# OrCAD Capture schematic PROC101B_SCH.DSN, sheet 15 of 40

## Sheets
15 38. SoC POWER SUPPLY: size C; title: SoC POWER SUPPLY

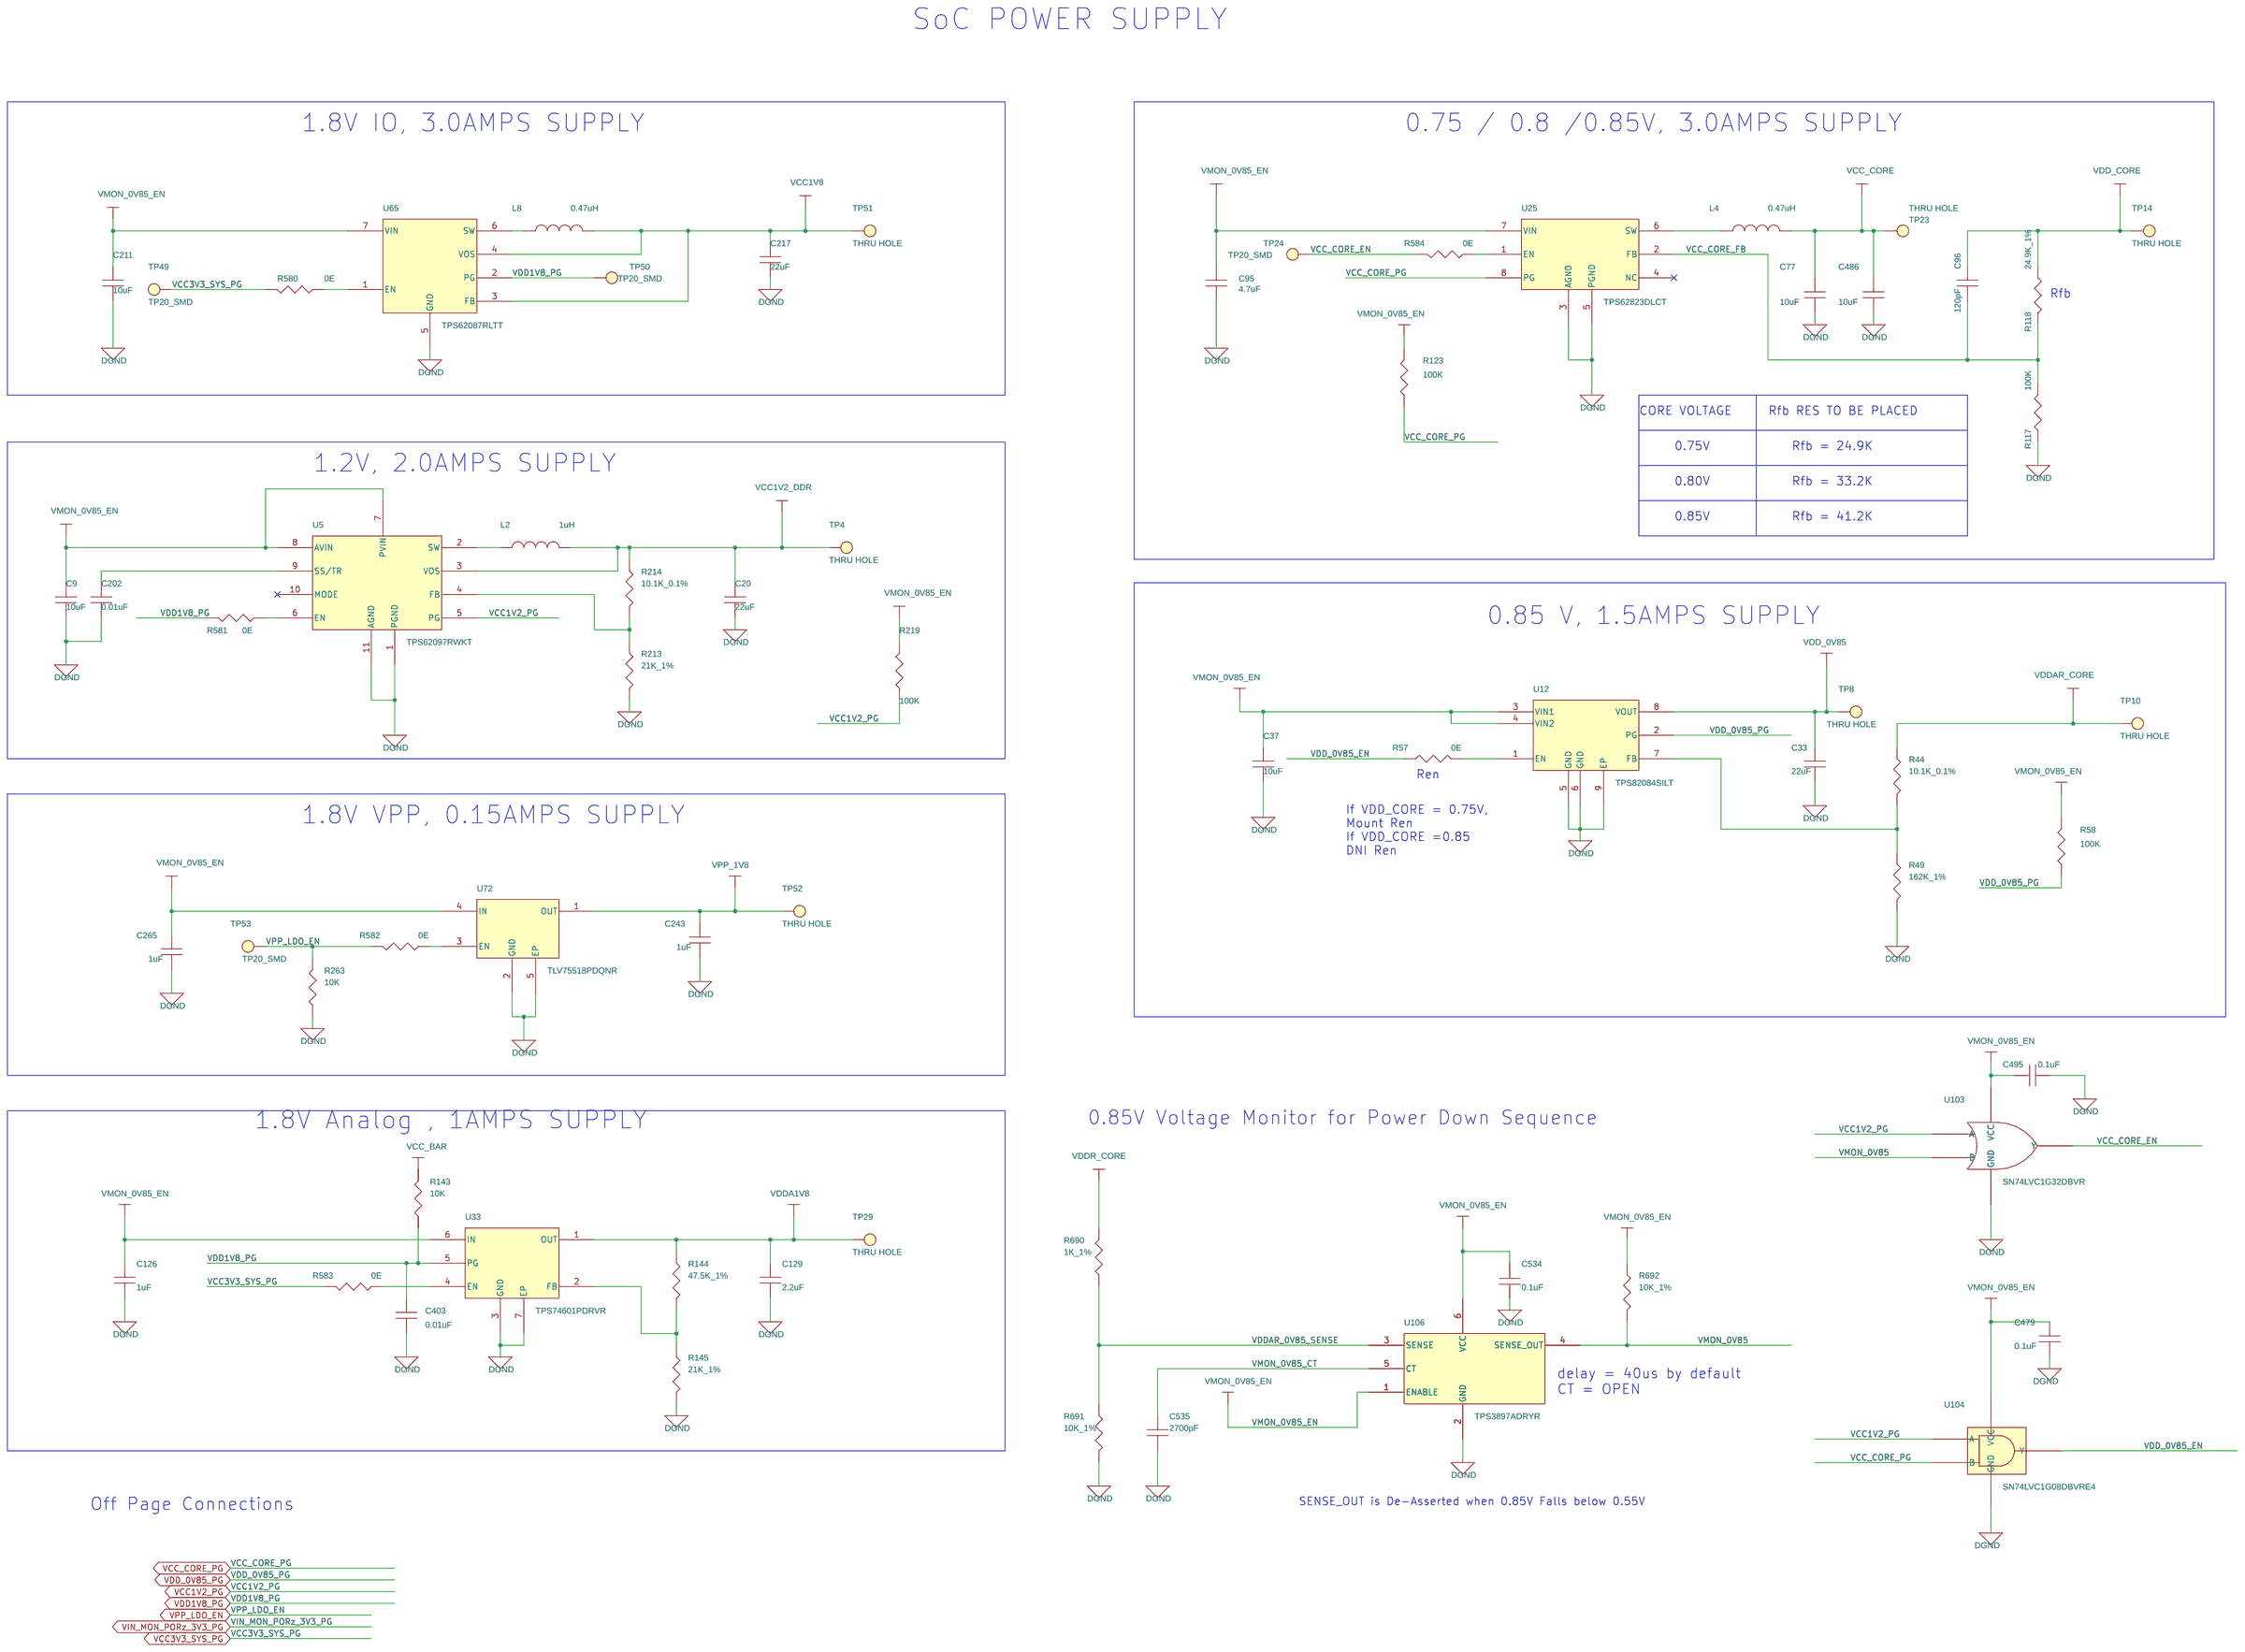
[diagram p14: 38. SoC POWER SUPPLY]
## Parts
C9  10uF  [CAP0402_0-75]
C20  22uF  [CAP0603_1]
C33  22uF  [CAP0603_1]
C37  10uF  [CAP0402_0-75]
C77  10uF  [CAP0402_0-75]
C95  4.7uF  [CAP0603_1]
C96  120pF  [CAP0402_0-75]
C126  1uF  [CAP0402_0-75]
C129  2.2uF  [CAP0402_0-75]
C202  0.01uF  [CAP0402_0-75]
C211  10uF  [CAP0603_1]
C217  22uF  [CAP0603_1]
C243  1uF  [CAP0402_0-75]
C265  1uF  [CAP0402_0-75]
C403  0.01uF  [CAP0402_0-75]
C479  0.1uF  [CAP0402_0-75]
C486  10uF  [CAP0402_0-75]
C495  0.1uF  [CAP0402_0-75]
C534  0.1uF  [CAP0402_0-75]
C535  2700pF  [CAP0603_1]
L2  1uH  [IND_744316100_230X220_SMD_4-3]
L4  0.47uH  [IND_744373460047_270X270_SMD_3]
L8  0.47uH  [IND_744373460047_270X270_SMD_3]
R44  10.1K_0.1%  [RES0603_0-75]
R49  162K_1%  [RES0402_0-5]
R57  0E  [RES0402_0-5]
R58  100K  [RES0402_0-5]
R117  100K  [RES0402_0-5]
R118  24.9K_1%  [RES0402_0-5]
R123  100K  [RES0402_0-5]
R143  10K  [RES0402_0-5]
R144  47.5K_1%  [RES0402_0-5]
R145  21K_1%  [RES0402_0-5]
R213  21K_1%  [RES0402_0-5]
R214  10.1K_0.1%  [RES0603_0-75]
R219  100K  [RES0402_0-5]
R263  10K  [RES0402_0-5]
R580  0E  [RES0402_0-5]
R581  0E  [RES0402_0-5]
R582  0E  [RES0402_0-5]
R583  0E  [RES0402_0-5]
R584  0E  [RES0402_0-5]
R690  1K_1%  [RES0402_0-5]
R691  10K_1%  [RES0402_0-5]
R692  10K_1%  [RES0402_0-5]
TP4  THRU HOLE  [TP_40X65]
TP8  THRU HOLE  [TP_40X65]
TP10  THRU HOLE  [TP_40X65]
TP14  THRU HOLE  [TP_40X65]
TP23  THRU HOLE  [TP_40X65]
TP24  TP20_SMD  [TP20_SMD]
TP29  THRU HOLE  [TP_40X65]
TP49  TP20_SMD  [TP20_SMD]
TP50  TP20_SMD  [TP20_SMD]
TP51  THRU HOLE  [TP_40X65]
TP52  THRU HOLE  [TP_40X65]
TP53  TP20_SMD  [TP20_SMD]
U5  TPS62097RWKT  [VQFNHR11_TPS62097_80X80_1]
U12  TPS82084SILT  [uSIP8_TPS82084_110X120_1-4]
U25  TPS62823DLCT  [VSONHR8_TPS62823_60X80_1]
U33  TPS74601PDRVR  [SON6_25-59_85X85_0-8]
U65  TPS62087RLTT  [VSONHR7_TPS62085_80X80_1]
U72  TLV75518PDQNR  [X2SON4_TLV71318P_40X40_0-4]
U103  SN74LVC1G32DBVR  [SOT23-5_1-5]
U104  SN74LVC1G08DBVRE4  [SOT23-5]
U106  TPS3897ADRYR  [SON6_19-68_40X60_0-6]

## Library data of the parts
C9 C37 C77 C486 = CAP: CAP CERAMIC 10uF 10V 20% X5R 0402; Chkd/date: MANIRAJA/300520; Crtd /date: ALVY/260520; Custom_Duty: 15%; Customs_HS_Code: 85322990; Distributor_name: DIGIKEY; Distributor_part_number: 490-GRM155R61A106ME11DTR-ND; Footprint Path: Y:\MIS_DATABASE\Library\ALTIUM_TOOL\PCB_FOOTPRINTS\Altium_Footprint_Lib.PcbLib; Height: 0.55MM; Library Path: Y:\MIS_DATABASE\Library\ALTIUM_TOOL\SCHEMATICS_PARTS\MS_DISCRETE_Library.schlib; Mfr_name: MURATA; Mfr_part_number: GRM155R61A106ME11D; Mistral Part No: 120013110019-R; Package: 0402; Part_type: CAPACITORS\CERAMIC; Project: QCS610_NANOSOM; RoHS: RoHS; Temperature: -55°C+85°C; Tolerance: 20%; Voltage: 10V; Wattage: NA; Weight: 3.1mg; Datasheet: Y:\MIS_DATABASE\DATASHEETS\CAPACITORS\MURATA-GXX-SER_NOV17.PDF
C20 C33 C217 = CAP: CAP CERAMIC 22uF 6.3V 20% X5R 0603; Chkd/date: JEBRAN/090915; Crtd /date: JEBRAN/090915; Custom_Duty: 15%; Customs_HS_Code: 85322990; Distributor_name: DIGIKEY; Distributor_part_number: 490-7611-2-ND; Footprint Path: Y:\MIS_DATABASE\Library\ALTIUM_TOOL\PCB_FOOTPRINTS\Altium_Footprint_Lib.PcbLib; Height: 1.00MM; Library Path: Y:\MIS_DATABASE\Library\ALTIUM_TOOL\SCHEMATICS_PARTS\MS_DISCRETE_Library.schlib; Mfr_name: MURATA; Mfr_part_number: GRM188R60J226MEA0; Mistral Part No: 120015090007-R; Package: 0603; Part_type: CAPACITORS\CERAMIC; Project: OCTBTS_3000; RoHS: RoHS; Temperature: -55°C+85°C; Tolerance: 20%; Voltage: 6.3V; Wattage: NA; Weight: 6.3mg; Datasheet: Y:\MIS_DATABASE\DATASHEETS\CAPACITORS\MURATA-GXX-SER_NOV17.PDF
C95 = CAP: CAP CERAMIC 4.7uF 16V 10% X5R 0603; Chkd/date: MANIRAJA/131217; Crtd /date: ALVY/131217; Custom_Duty: 15%; Customs_HS_Code: 85322990; Distributor_name: DIGIKEY; Distributor_part_number: 311-1785-1-ND; Footprint Path: Y:\MIS_DATABASE\Library\ALTIUM_TOOL\PCB_FOOTPRINTS\Altium_Footprint_Lib.PcbLib; Height: 0.95MM; Library Path: Y:\MIS_DATABASE\Library\ALTIUM_TOOL\SCHEMATICS_PARTS\MS_DISCRETE_Library.schlib; Mfr_name: YAGEO AMERICA; Mfr_part_number: CC0603KRX5R7BB475; Mistral Part No: 120011050004-R; Package: 0603; Part_type: CAPACITORS\CERAMIC; Project: ASL_LIU_TYPE-II; RoHS: RoHS; Temperature: -55°C+85°C; Tolerance: 10%; Voltage: 16V; Wattage: NA; Weight: 2mg; Datasheet: Y:\MIS_DATABASE\DATASHEETS\CAPACITORS\YACC-X5R.PDF
C96 = CAP: CAP CERAMIC 120pF 50V 5% C0G(NP0) 0402; Chkd/date: MANIRAJA/080520; Crtd /date: ALVY/070520; Custom_Duty: 15%; Customs_HS_Code: 85322990; Distributor_name: DIGIKEY; Distributor_part_number: 311-3337-1-ND; Footprint Path: Y:\MIS_DATABASE\Library\ALTIUM_TOOL\PCB_FOOTPRINTS\Altium_Footprint_Lib.PcbLib; Height: 0.55MM; Library Path: Y:\MIS_DATABASE\Library\ALTIUM_TOOL\SCHEMATICS_PARTS\MS_DISCRETE_Library.schlib; Mfr_name: YAGEO AMERICA; Mfr_part_number: CC0402JRNPO9BN121; Mistral Part No: 120014040005-R; Package: 0402; Part_type: CAPACITORS\CERAMIC; Project: AM64x-GP_EVM BRD; RoHS: RoHS; Temperature: -55°C+125°C; Tolerance: 5%; Voltage: 50V; Wattage: NA; Weight: 12mg; Datasheet: Y:\MIS_DATABASE\DATASHEETS\CAPACITORS\YACC-NPO.PDF
C126 C243 C265 = CAP: CAP CERAMIC 1uF 10V 20% X5R 0402; Chkd/date: MANIRAJA/210820; Crtd /date: ALVY/190820; Custom_Duty: 15%; Customs_HS_Code: 85322990; Distributor_name: DIGIKEY; Distributor_part_number: 732-7489-1-ND; Footprint Path: Y:\MIS_DATABASE\Library\ALTIUM_TOOL\PCB_FOOTPRINTS\Altium_Footprint_Lib.PcbLib; Height: 0.55MM; Library Path: Y:\MIS_DATABASE\Library\ALTIUM_TOOL\SCHEMATICS_PARTS\MS_DISCRETE_Library.schlib; Mfr_name: WURTH ELECTRONICS; Mfr_part_number: 885012105012; Mistral Part No: 120020080009-R; Package: 0402; Part_type: CAPACITORS\CERAMIC; Project: AM64x_EVM_BRD; RoHS: RoHS; Temperature: -55°C+85°C; Tolerance: 20%; Voltage: 10V; Wattage: NA; Weight: 0.65mg; Datasheet: Y:\MIS_DATABASE\DATASHEETS\CAPACITORS\885012105012.PDF
C129 = CAP: CAP CERAMIC 2.2uF 10V 20% X5R 0402; Chkd/date: MANIRAJA/170820; Crtd /date: ALVY/170820; Custom_Duty: 15%; Customs_HS_Code: 85322990; Distributor_name: DIGIKEY; Distributor_part_number: 732-7490-1-ND; Footprint Path: Y:\MIS_DATABASE\Library\ALTIUM_TOOL\PCB_FOOTPRINTS\Altium_Footprint_Lib.PcbLib; Height: 0.55MM; Library Path: Y:\MIS_DATABASE\Library\ALTIUM_TOOL\SCHEMATICS_PARTS\MS_DISCRETE_Library.schlib; Mfr_name: WURTH ELECTRONICS; Mfr_part_number: 885012105013; Mistral Part No: 120019040036-R; Package: 0402; Part_type: CAPACITORS\CERAMIC; Project: AM64x_EVM_BRD; RoHS: RoHS; Temperature: -55°C+85°C; Tolerance: 20%; Voltage: 10V; Wattage: NA; Weight: 0.65mg; Datasheet: Y:\MIS_DATABASE\DATASHEETS\CAPACITORS\885012105013.PDF
C202 C403 = CAP: CAP CERAMIC 0.01uF 25V 10% X7R 0402; Chkd/date: MANIRAJA/170820; Crtd /date: ALVY/170820; Custom_Duty: 15%; Customs_HS_Code: 85322990; Distributor_name: DIGIKEY; Distributor_part_number: 732-7545-1-ND; Footprint Path: Y:\MIS_DATABASE\Library\ALTIUM_TOOL\PCB_FOOTPRINTS\Altium_Footprint_Lib.PcbLib; Height: 0.55MM; Library Path: Y:\MIS_DATABASE\Library\ALTIUM_TOOL\SCHEMATICS_PARTS\MS_DISCRETE_Library.schlib; Mfr_name: WURTH ELECTRONICS; Mfr_part_number: 885012205050; Mistral Part No: 120011090040-R; Package: 0402; Part_type: CAPACITORS\CERAMIC; Project: AM64x_EVM_BRD; RoHS: RoHS; Temperature: -55°C+125°C; Tolerance: 10%; Voltage: 25V; Wattage: NA; Weight: 0.65mg; Datasheet: Y:\MIS_DATABASE\DATASHEETS\CAPACITORS\885012205050.PDF
C211 = CAP: CAP CERAMIC 10uF 35V 20% X5R 0603; Chkd/date: MANIRAJA/170519; Crtd /date: ALVY/160519; Custom_Duty: 15%; Customs_HS_Code: 85322990; Distributor_name: DIGIKEY; Distributor_part_number: 490-13248-1-ND; Footprint Path: Y:\MIS_DATABASE\Library\ALTIUM_TOOL\PCB_FOOTPRINTS\Altium_Footprint_Lib.PcbLib; Height: 1.00MM; Library Path: Y:\MIS_DATABASE\Library\ALTIUM_TOOL\SCHEMATICS_PARTS\MS_DISCRETE_Library.schlib; Mfr_name: MURATA; Mfr_part_number: GRM188R6YA106MA73D; Mistral Part No: 120019050016-R; Package: 0603; Part_type: CAPACITORS\CERAMIC; Project: BRUKER_SD820_COMMONDO; RoHS: RoHS; Temperature: -55°C+85°C; Tolerance: 20%; Voltage: 35V; Wattage: NA; Weight: 9mg; Datasheet: Y:\MIS_DATABASE\DATASHEETS\CAPACITORS\GRM188R6YA106MA73.PDF
C479 C495 C534 = CAP: CAP CERAMIC 0.1uF 25V 20% X5R 0402; Alt_Mfr_name: YAGEO AMERICA; Alt_Mfr_part_number: CC0402KRX5R8BB104; Chkd/date: MANIRAJA/170820; Crtd /date: ALVY/170820; Custom_Duty: 15%; Customs_HS_Code: 85322990; Distributor_name: DIGIKEY; Distributor_part_number: 732-7495-1-ND; Footprint Path: Y:\MIS_DATABASE\Library\ALTIUM_TOOL\PCB_FOOTPRINTS\Altium_Footprint_Lib.PcbLib; Height: 0.55MM; Library Path: Y:\MIS_DATABASE\Library\ALTIUM_TOOL\SCHEMATICS_PARTS\MS_DISCRETE_Library.schlib; Mfr_name: WURTH ELECTRONICS; Mfr_part_number: 885012105018; Mistral Part No: 120020080003-R; Package: 0402; Part_type: CAPACITORS\CERAMIC; Project: AM64x_EVM_BRD; RoHS: RoHS; Temperature: -55°C+85°C; Tolerance: 20%; Voltage: 25V; Wattage: NA; Weight: 0.65mg; Datasheet: Y:\MIS_DATABASE\DATASHEETS\CAPACITORS\885012105018.PDF
C535 = CAP: CAP CERAMIC 2700pF 50V 5% C0G(NP0) 0603; Chkd/date: BAVISH/050911; Crtd /date: CHAITHANYA/290811; Custom_Duty: 15%; Customs_HS_Code: 85322990; Distributor_name: DIGIKEY; Distributor_part_number: 490-3283-1-ND; Footprint Path: Y:\MIS_DATABASE\Library\ALTIUM_TOOL\PCB_FOOTPRINTS\Altium_Footprint_Lib.PcbLib; Height: 0.90MM; Library Path: Y:\MIS_DATABASE\Library\ALTIUM_TOOL\SCHEMATICS_PARTS\MS_DISCRETE_Library.schlib; Mfr_name: MURATA; Mfr_part_number: GRM1885C1H272JA01D; Mistral Part No: 120011090002-R; Package: 0603; Part_type: CAPACITORS\CERAMIC; Project: GEMYC; RoHS: RoHS; Temperature: -55°C+125°C; Tolerance: 5%; Voltage: 50V; Wattage: NA; Weight: 6.3mg; Datasheet: Y:\MIS_DATABASE\DATASHEETS\CAPACITORS\MURATA-GXX-SER_NOV17.PDF
L2 = INDUCTOR: IND HI-CURRENT 1uH 11.5A 20% SMD; Chkd/date: MANIRAJA/280520; Crtd /date: ALVY/280520; Custom_Duty: 24%; Customs_HS_Code: 85437099; Distributor_name: DIGIKEY; Distributor_part_number: 732-6176-1-ND; Footprint Path: Y:\MIS_DATABASE\Library\ALTIUM_TOOL\PCB_FOOTPRINTS\Altium_Footprint_Lib.PcbLib; Height: 4.30MM; Library Path: Y:\MIS_DATABASE\Library\ALTIUM_TOOL\SCHEMATICS_PARTS\MS_DISCRETE_Library.schlib; Mfr_name: WURTH ELECTRONICS; Mfr_part_number: 744316100; Mistral Part No: 130020050041-R; Package: SMD; Project: AM64x-GP_EVM BRD; RoHS: RoHS; Temperature: -40°C+150°C; Tolerance: 20%; Voltage: NA; Wattage: NA; Weight: 570mg; Datasheet: Y:\MIS_DATABASE\DATASHEETS\DISCRETES\INDUCTORS\744316100.PDF
L4 L8 = INDUCTOR: IND POWER 0.47uH 11.5A 20% SMD; Chkd/date: MANIRAJA/130820; Crtd /date: ALVY/130820; Custom_Duty: 24%; Customs_HS_Code: 85437099; Distributor_name: DIGIKEY; Distributor_part_number: 732-3366-1-ND; Footprint Path: Y:\MIS_DATABASE\Library\ALTIUM_TOOL\PCB_FOOTPRINTS\Altium_Footprint_Lib.PcbLib; Height: 3.00MM; Library Path: Y:\MIS_DATABASE\Library\ALTIUM_TOOL\SCHEMATICS_PARTS\MS_DISCRETE_Library.schlib; Mfr_name: WURTH ELECTRONICS; Mfr_part_number: 744373460047; Mistral Part No: 130020080011-R; Package: SMD; Project: AM64x_EVM_BRD; RoHS: RoHS; Temperature: -40°C+125°C; Tolerance: 20%; Voltage: NA; Wattage: NA; Weight: 719mg; Datasheet: Y:\MIS_DATABASE\DATASHEETS\DISCRETES\INDUCTORS\744373460047.PDF
R44 R214 = RESISTOR: RES 10.1K 1/8W 0.1% AUTO 0603; Chkd/date: MANIRAJA/090420; Crtd /date: ALVY/080420; Custom_Duty: 15%; Customs_HS_Code: 85332119; Distributor_name: DIGIKEY; Distributor_part_number: 541-3907-1-ND; Footprint Path: Y:\MIS_DATABASE\Library\ALTIUM_TOOL\PCB_FOOTPRINTS\Altium_Footprint_Lib.PcbLib; Height: 0.55MM; Library Path: Y:\MIS_DATABASE\Library\ALTIUM_TOOL\SCHEMATICS_PARTS\MS_DISCRETE_Library.schlib; Mfr_name: VISHAY; Mfr_part_number: TNPW060310K1BEEA; Mistral Part No: 110020040008-R; Package: 0603; Part_type: RESISTORS\FIXED; Project: AM64x-GP_EVM BRD; RoHS: RoHS; Temperature: -55°C+155°C; Tolerance: 0.1%; Voltage: NA; Wattage: 1/8W; Weight: 25mg; Datasheet: Y:\MIS_DATABASE\DATASHEETS\RESISTORS\VISHAY_TNPWE3.PDF
R49 = RESISTOR: RES 162K 1/10W 1% 0402; Chkd/date: SUHAS/270910; Crtd /date: MUDDU/190610; Custom_Duty: 15%; Customs_HS_Code: 85332119; Distributor_name: DIGIKEY; Distributor_part_number: P162KLCT-ND; Footprint Path: Y:\MIS_DATABASE\Library\ALTIUM_TOOL\PCB_FOOTPRINTS\Altium_Footprint_Lib.PcbLib; Height: 0.40MM; Library Path: Y:\MIS_DATABASE\Library\ALTIUM_TOOL\SCHEMATICS_PARTS\MS_DISCRETE_Library.schlib; Mfr_name: PANASONIC-ECG; Mfr_part_number: ERJ-2RKF1623X; Mistral Part No: 110010060019-R; Package: 0402; Part_type: RESISTORS\FIXED; Project: CENTAURUS; RoHS: RoHS; Temperature: -55°C+155°C; Tolerance: 1%; Voltage: NA; Wattage: 1/10W; Weight: 0.8mg; Datasheet: Y:\MIS_DATABASE\DATASHEETS\RESISTORS\PAN-ERJSER_NOV17.PDF
R57 R580-R584 = RESISTOR: RES 0E 1/16W JUMPER 0402; Chkd/date: VASANTHA/201216; Crtd /date: MUDDU/190810; Custom_Duty: 15%; Customs_HS_Code: 85332119; Distributor_name: DIGIKEY; Distributor_part_number: 541-0.0JCT-ND; Footprint Path: Y:\MIS_DATABASE\Library\ALTIUM_TOOL\PCB_FOOTPRINTS\Altium_Footprint_Lib.PcbLib; Height: 0.40MM; Library Path: Y:\MIS_DATABASE\Library\ALTIUM_TOOL\SCHEMATICS_PARTS\MS_DISCRETE_Library.schlib; Mfr_name: VISHAY; Mfr_part_number: CRCW04020000Z0ED; Mistral Part No: 110010080019-R; Package: 0402; Part_type: RESISTORS\FIXED; Project: PB_BUGBASE; RoHS: RoHS; Temperature: -55°C+155°C; Tolerance: NA; Voltage: NA; Wattage: 1/16W; Weight: 0.65mg; Datasheet: Y:\MIS_DATABASE\DATASHEETS\RESISTORS\CRCW0603.PDF
R58 R117 R123 R219 = RESISTOR: RES 100K 1/16W 5% 0402; Chkd/date: VASANTHA/061216; Crtd /date: BAVISH/010611; Custom_Duty: 15%; Customs_HS_Code: 85332119; Distributor_name: DIGIKEY; Distributor_part_number: 541-100KJCT-ND; Footprint Path: Y:\MIS_DATABASE\Library\ALTIUM_TOOL\PCB_FOOTPRINTS\Altium_Footprint_Lib.PcbLib; Height: 0.40MM; Library Path: Y:\MIS_DATABASE\Library\ALTIUM_TOOL\SCHEMATICS_PARTS\MS_DISCRETE_Library.schlib; Mfr_name: VISHAY; Mfr_part_number: CRCW0402100KJNED; Mistral Part No: 110011060002-R; Package: 0402; Part_type: RESISTORS\FIXED; Project: AM4515_EVM_LCD; RoHS: RoHS; Temperature: -55°C+155°C; Tolerance: 5%; Voltage: NA; Wattage: 1/16W; Weight: 0.65mg; Datasheet: Y:\MIS_DATABASE\DATASHEETS\RESISTORS\CRCW0603.PDF
R118 = RESISTOR: RES 24.9K 1/16W 1% 0402; Chkd/date: MANIRAJA/080520; Crtd /date: ALVY/070520; Custom_Duty: 15%; Customs_HS_Code: 85332119; Distributor_name: DIGIKEY; Distributor_part_number: 541-24.9KLCT-ND; Footprint Path: Y:\MIS_DATABASE\Library\ALTIUM_TOOL\PCB_FOOTPRINTS\Altium_Footprint_Lib.PcbLib; Height: 0.40MM; Library Path: Y:\MIS_DATABASE\Library\ALTIUM_TOOL\SCHEMATICS_PARTS\MS_DISCRETE_Library.schlib; Mfr_name: VISHAY; Mfr_part_number: CRCW040224K9FKED; Mistral Part No: 110009030538-R; Package: 0402; Part_type: RESISTORS\FIXED; Project: AM64x-GP_EVM BRD; RoHS: RoHS; Temperature: -55°C+155°C; Tolerance: 1%; Voltage: NA; Wattage: 1/16W; Weight: 0.65mg; Datasheet: Y:\MIS_DATABASE\DATASHEETS\RESISTORS\CRCW0603.PDF
R143 R263 = RESISTOR: RES 10K 1/16W 5% 0402; Chkd/date: VASANTHA/061216; Crtd /date: MAZHAR/230805; Custom_Duty: 15%; Customs_HS_Code: 85332119; Distributor_name: DIGIKEY; Distributor_part_number: 311-10KJRCT-ND; Footprint Path: Y:\MIS_DATABASE\Library\ALTIUM_TOOL\PCB_FOOTPRINTS\Altium_Footprint_Lib.PcbLib; Height: 0.40MM; Library Path: Y:\MIS_DATABASE\Library\ALTIUM_TOOL\SCHEMATICS_PARTS\MS_DISCRETE_Library.schlib; Mfr_name: YAGEO AMERICA; Mfr_part_number: RC0402JR-0710KL; Mistral Part No: 110011060021-R; Package: 0402; Part_type: RESISTORS\FIXED; Project: HSE; RoHS: RoHS; Temperature: -55°C+155°C; Tolerance: 5%; Voltage: NA; Wattage: 1/16W; Weight: 0.65mg; Datasheet: Y:\MIS_DATABASE\DATASHEETS\RESISTORS\RCXXXXL-SER_MAR18.PDF
R144 = RESISTOR: RES 47.5K 1/16W 1% 0402; Chkd/date: MANIRAJA/170320; Crtd /date: MANIRAJA/170320; Custom_Duty: 15%; Customs_HS_Code: 85332119; Distributor_name: DIGIKEY; Distributor_part_number: 541-47.5KLCT-ND; Footprint Path: Y:\MIS_DATABASE\Library\ALTIUM_TOOL\PCB_FOOTPRINTS\Altium_Footprint_Lib.PcbLib; Height: 0.40MM; Library Path: Y:\MIS_DATABASE\Library\ALTIUM_TOOL\SCHEMATICS_PARTS\MS_DISCRETE_Library.schlib; Mfr_name: VISHAY; Mfr_part_number: CRCW040247K5FKED; Mistral Part No: 110017010006-R; Package: 0402; Part_type: RESISTORS\FIXED; Project: TPR12_SVB; RoHS: RoHS; Temperature: -55°C+155°C; Tolerance: 1%; Voltage: NA; Wattage: 1/16W; Weight: 0.65mg; Datasheet: Y:\MIS_DATABASE\DATASHEETS\RESISTORS\CRCW0603.PDF
R145 R213 = RESISTOR: RES 21K 1/16W 1% 0402; Chkd/date: MANIRAJA/200319; Crtd /date: MANIRAJA/200319; Custom_Duty: 15%; Customs_HS_Code: 85332119; Distributor_name: DIGIKEY; Distributor_part_number: 311-21.0KLRCT-ND; Footprint Path: Y:\MIS_DATABASE\Library\ALTIUM_TOOL\PCB_FOOTPRINTS\Altium_Footprint_Lib.PcbLib; Height: 0.40MM; Library Path: Y:\MIS_DATABASE\Library\ALTIUM_TOOL\SCHEMATICS_PARTS\MS_DISCRETE_Library.schlib; Mfr_name: YAGEO AMERICA; Mfr_part_number: RC0402FR-0721KL; Mistral Part No: 110015080019-R; Package: 0402; Part_type: RESISTORS\FIXED; Project: OCTASIC_3000; RoHS: RoHS; Temperature: -55°C+155°C; Tolerance: 1%; Voltage: NA; Wattage: 1/16W; Weight: 0.65mg; Datasheet: Y:\MIS_DATABASE\DATASHEETS\RESISTORS\RCXXXXL-SER_MAR18.PDF
R690 = RESISTOR: RES 1K 1/10W 1% 0402; Chkd/date: VASANTHA/281216; Crtd /date: MAZHAR/150506; Custom_Duty: 15%; Customs_HS_Code: 85332119; Distributor_name: DIGIKEY; Distributor_part_number: P1.00KLCT-ND; Footprint Path: Y:\MIS_DATABASE\Library\ALTIUM_TOOL\PCB_FOOTPRINTS\Altium_Footprint_Lib.PcbLib; Height: 0.40MM; Library Path: Y:\MIS_DATABASE\Library\ALTIUM_TOOL\SCHEMATICS_PARTS\MS_DISCRETE_Library.schlib; Mfr_name: PANASONIC-ECG; Mfr_part_number: ERJ-2RKF1001X; Mistral Part No: 110009030411-R; Package: 0402; Part_type: RESISTORS\FIXED; Project: VOCERA; RoHS: RoHS; Temperature: -55°C+155°C; Tolerance: 1%; Voltage: NA; Wattage: 1/10W; Weight: 0.8mg; Datasheet: Y:\MIS_DATABASE\DATASHEETS\RESISTORS\PAN-ERJSER_NOV17.PDF
R691 R692 = RESISTOR: RES 10K 1/16W 1% 0402; Chkd/date: VASANTHA/201216; Crtd /date: GEETHA/290506; Custom_Duty: 15%; Customs_HS_Code: 85332119; Distributor_name: DIGIKEY; Distributor_part_number: 311-10.0KLRTR-ND; Footprint Path: Y:\MIS_DATABASE\Library\ALTIUM_TOOL\PCB_FOOTPRINTS\Altium_Footprint_Lib.PcbLib; Height: 0.40MM; Library Path: Y:\MIS_DATABASE\Library\ALTIUM_TOOL\SCHEMATICS_PARTS\MS_DISCRETE_Library.schlib; Mfr_name: YAGEO AMERICA; Mfr_part_number: RC0402FR-0710KL; Mistral Part No: 110015090015-R; Package: 0402; Part_type: RESISTORS\FIXED; Project: VOCERA; RoHS: RoHS; Temperature: -55°C+155°C; Tolerance: 1%; Voltage: NA; Wattage: 1/16W; Weight: 0.65mg; Datasheet: Y:\MIS_DATABASE\DATASHEETS\RESISTORS\RCXXXXL-SER_MAR18.PDF
TP4 TP8 TP10 TP14 TP23 TP29 TP51 TP52 = TESTPOINT: TESTPOINT 1.0MM DRILL PTH; Chkd/date: MAZHAR/271211; Crtd /date: SHREESHAIL/041005; Distributor_name: NA; Distributor_part_number: NA; Height: NA; Mfr_name: LOCAL; Mistral Part No: 130009030938; Package: THRU-HOLE; Project: HSE; Datasheet: NA
TP24 TP49 TP50 TP53 = TESTPOINT: TESTPOINT CIR 20 SMD; Chkd/date: SHREESHAIL/171006; Crtd /date: MAZHAR/171006; Custom_Duty: NA; Customs_HS_Code: NA; Distributor_name: NA; Distributor_part_number: NA; Footprint Path: Y:\MIS_DATABASE\Library\ALTIUM_TOOL\PCB_FOOTPRINTS\Altium_Footprint_Lib.PcbLib; Height: NA; Library Path: Y:\MIS_DATABASE\Library\ALTIUM_TOOL\SCHEMATICS_PARTS\MS_DISCRETE_Library.schlib; MECHANICAL 3D STEP FILE: NA; Mfr_name: LOCAL; Mistral Part No: NA; Package: SMD; Project: BT MODULE_CSRBC04; RoHS: NA; Temperature: NA; Tolerance: NA; Voltage: NA; Wattage: NA; Weight: NA; Datasheet: NA
U5 = TPS62097RWKT_VQFNHR11: IC 2A SYNCHRONOUS STEP DOWN CONVERTER WITH IDCS CONTROL VQFN-HR11; Chkd/date: MANIRAJA/270917; Crtd /date: MANIRAJA/270917; Custom_Duty: 15%; Customs_HS_Code: 85423100; Distributor_name: DIGIKEY; Distributor_part_number: 296-43330-1-ND; Height: 1.00MM; Mfr_name: TEXAS INSTRUMENTS; Mistral Part No: 142017090025-R; Package: VQFN-HR11; Part_type: ICS\POWER\CONVERTER; Project: TI_MAXIE_CPB; RoHS: RoHS; Temperature: -40°C+125°C; Tolerance: NA; Voltage: NA; Wattage: NA; Weight: NA; Datasheet: Y:\MIS_DATABASE\DATASHEETS\ICS\POWER\TPS62097.PDF
U12 = TPS82084_USIP8: IC 2A STEP DOWN CONVERTER MICROSIP POWER MODULE WITH INTEGRATED INDUCTOR uSIP8; Chkd/date: MANIRAJA/090420; Crtd /date: ALVY/080420; Custom_Duty: 15%; Customs_HS_Code: 85423100; Distributor_name: DIGIKEY; Distributor_part_number: 296-42973-1-ND; Footprint Path: Y:\MIS_DATABASE\Library\ALTIUM_TOOL\PCB_FOOTPRINTS\Altium_Footprint_Lib.PcbLib; Height: 1.33MM; Library Path: Y:\MIS_DATABASE\Library\ALTIUM_TOOL\SCHEMATICS_PARTS\MS_MISCPOWER_Library.schlib; Library Ref: TPS82084_uSIP8; Mfr_name: TEXAS INSTRUMENTS; Mistral Part No: 142020040012-R; Package: uSIP8; Part_type: ICS\POWER\POWER MODULE; Project: AM64x-GP_EVM BRD; RoHS: RoHS; Temperature: -40°C+125°C; Tolerance: NA; Voltage: NA; Wattage: NA; Weight: 580mg; Datasheet: Y:\MIS_DATABASE\DATASHEETS\ICS\POWER\TPS8208X.PDF
U25 = TPS62823_VSONHR8: IC 3A ADJ STEP-DOWN CONVERTER WITH 1% ACCURACY VSON-HR8; Chkd/date: MANIRAJA/080520; Crtd /date: ALVY/070520; Custom_Duty: 15%; Customs_HS_Code: 85423100; Distributor_name: DIGIKEY; Distributor_part_number: 296-50225-1-ND; Footprint Path: Y:\MIS_DATABASE\Library\ALTIUM_TOOL\PCB_FOOTPRINTS\Altium_Footprint_Lib.PcbLib; Height: 1.00MM; Library Path: Y:\MIS_DATABASE\Library\ALTIUM_TOOL\SCHEMATICS_PARTS\MS_MISCPOWER_Library.schlib; Mfr_name: TEXAS INSTRUMENTS; Mistral Part No: 142020050005-R; Package: VSON-HR8; Part_type: ICS\POWER\DC-DC CONVERTER; Project: AM64x-GP_EVM BRD; RoHS: RoHS; Temperature: -40°C+125°C; Tolerance: NA; Voltage: NA; Wattage: NA; Weight: 6.2mg; Datasheet: Y:\MIS_DATABASE\DATASHEETS\ICS\POWER\TPS62821-2-3.PDF
U33 = TPS74501_WSON6: IC 1A ADJ OUTPUT LDO WITH POWER-GOOD WSON6; Chkd/date: MANIRAJA/060619; Crtd /date: ALVY/060619; Custom_Duty: 15%; Customs_HS_Code: 85423100; Distributor_name: MOUSER; Distributor_part_number: 595-TPS74601PDRVR; Footprint Path: Y:\MIS_DATABASE\Library\ALTIUM_TOOL\PCB_FOOTPRINTS\Altium_Footprint_Lib.PcbLib; Height: 0.80MM; Library Path: Y:\MIS_DATABASE\Library\ALTIUM_TOOL\SCHEMATICS_PARTS\MS_MISCPOWER_Library.schlib; Mfr_name: TEXAS INSTRUMENTS; Mistral Part No: 142019060004-R; Package: WSON6; Part_type: ICS\POWER\VOLTAGE REGULATOR; Project: TI_MAXIE_CPB; RoHS: RoHS; Temperature: -40°C+125°C; Tolerance: NA; Voltage: NA; Wattage: NA; Weight: NA; Datasheet: Y:\MIS_DATABASE\DATASHEETS\ICS\POWER\TPS74601.PDF
U65 = TPS62085RLTR_VSONHR7: IC 3A 1.8V STEP DOWN CONVERTER WITH SHORT CIRCUIT PROTECTION VSON-HR7; Chkd/date: MANIRAJA/310818; Crtd /date: MANIRAJA/310818; Custom_Duty: 15%; Customs_HS_Code: 85423100; Distributor_name: DIGIKEY; Distributor_part_number: 296-37087-1-ND; Footprint Path: Y:\MIS_DATABASE\Library\ALTIUM_TOOL\PCB_FOOTPRINTS\Altium_Footprint_Lib.PcbLib; Height: 1.00MM; Library Path: Y:\MIS_DATABASE\Library\ALTIUM_TOOL\SCHEMATICS_PARTS\MS_MISCPOWER_Library.schlib; Mfr_name: TEXAS INSTRUMENTS; Mistral Part No: 142018080020-R; Package: VSON-HR7; Part_type: ICS\POWER\CONVERTER; Project: TI_MAXIE_CPB; RoHS: RoHS; Temperature: -40°C+125°C; Tolerance: NA; Voltage: NA; Wattage: NA; Weight: 8.8mg; Datasheet: Y:\MIS_DATABASE\DATASHEETS\ICS\POWER\TPS62085.PDF
U72 = TLV71318PDQNR_X2SON4: IC 500mA LOW IQ LDO REGULATOR X2SON-4; Crtd /date: ALVY/160620; Custom_Duty: 15%; Customs_HS_Code: 85423100; Distributor_name: DIGIKEY; Distributor_part_number: 296-51790-1-ND; Footprint Path: Y:\MIS_DATABASE\Library\ALTIUM_TOOL\PCB_FOOTPRINTS\Altium_Footprint_Lib.PcbLib; Height: 0.40MM; Library Path: Y:\MIS_DATABASE\Library\ALTIUM_TOOL\SCHEMATICS_PARTS\MS_MISCPOWER_Library.schlib; Mfr_name: TEXAS INSTRUMENTS; Mistral Part No: 142020060013-R; Package: X2SON-4; Part_type: ICS\POWER\VOLTAGE REGULATOR; Project: AM64x-GP_EVM BRD; RoHS: RoHS; Temperature: -40°C+125°C; Tolerance: NA; Voltage: NA; Wattage: NA; Weight: 1.1mg; Datasheet: Y:\MIS_DATABASE\DATASHEETS\ICS\POWER\TLV755P.PDF
U103 = SN74LVC1G32DBVR_SOT23-5: IC SINGAL 2 INPUT POSITIVE OR GATE SOT23-5; Chkd/date: MANIRAJA/051017; Crtd /date: MAZHAR/070806; Custom_Duty: 15%; Customs_HS_Code: 85423100; Distributor_name: DIGIKEY; Distributor_part_number: 296-9847-1-ND; Height: 1.45MM; Mfr_name: TEXAS INSTRUMENTS; Mistral Part No: 141009030236-R; Package: SOT23-5; Part_type: ICS\DIGITAL\GATES; Project: SVDO_RMB_MMA; RoHS: RoHS; Temperature: -40°C+85°C; Tolerance: NA; Voltage: NA; Wattage: NA; Weight: 6.3mg; Datasheet: Y:\MIS_DATABASE\DATASHEETS\ICS\DIGITAL\GATES\SN74LVC1G32.PDF
U104 = SN74LVC1G08DBVRE4_SOT23-5: IC SINGLE 2-INPUT POSITIVE AND GATE SOT23-5; Chkd/date: SUHAS/221010; Crtd /date: USMAN/151008; Custom_Duty: 15%; Customs_HS_Code: 85423100; Distributor_name: DIGIKEY; Distributor_part_number: SN74LVC1G08DBVRE4-ND; Height: 1.45MM; Mfr_name: TEXAS INSTRUMENTS; Mistral Part No: 141009060026-R; Part_type: ICS\DIGITAL\GATES; Project: KHAN_MAIN; RoHS: Sb/ Br FREE; Temperature: -40°C+85°C; Datasheet: Y:\MIS_DATABASE\DATASHEETS\ICS\DIGITAL\GATES\SN74LVC1G08.PDF
U106 = TPS3897ADRYR_SON6: IC 1-CH ADJ VOLTAGE MONITOR SON6; Chkd/date: MANIRAJA/091017; Crtd /date: MANIRAJA/091017; Custom_Duty: 15%; Customs_HS_Code: 85423100; Distributor_name: DIGIKEY; Distributor_part_number: 296-29810-1-ND; Height: 0.60MM; Mfr_name: TEXAS INSTRUMENTS; Mistral Part No: 142017100007-R; Package: SON6; Part_type: ICS\POWER\MANAGEMENT; Project: TI_MAXIE_CPB; RoHS: RoHS; Temperature: -40°C+125°C; Tolerance: NA; Voltage: NA; Wattage: NA; Weight: NA; Datasheet: Y:\MIS_DATABASE\DATASHEETS\ICS\POWER\TPS389X.PDF

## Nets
DGND: C9.2 C20.2 C33.2 C37.2 C77.2 C95.2 C126.2 C129.2 C202.2 C211.2 C217.2 C243.2 C265.2 C403.2 C479.2 C486.2 C495.1 C534.1 C535.2 R49.2 R117.1 R145.2 R213.2 R263.1 R691.2 U5.1(PGND) U5.11(AGND) U12.5(GND) U12.6(GND) U12.9(EP) U25.3(AGND) U25.5(PGND) U33.3(GND) U33.7(EP) U65.5(GND) U72.2(GND) U72.5(EP) U103.3(GND) U104.3(GND) U106.2(GND) ; also on sheet 2 3 4 5 6 7 8 9 10 11 12 13 14 16 17 18 19 20 21 22 23 24 25 26 27 28 29 30 39 40
VCC1V2_DDR: C20.1 L2.2 R214.1 TP4.1(TP) U5.3(VOS) ; also on sheet 14
VCC1V2_PG: R219.1 U5.5(PG) U103.1(A) U104.1(A) ; also on sheet 8
VCC1V8: C217.1 L8.2 TP51.1(TP) U65.3(FB) U65.4(VOS) ; also on sheet 11 12 13 14 18 21 24
VCC3V3_PREREG: C9.1 C37.1 C95.1 C126.1 C211.1 C265.1 C479.1 C495.2 C534.2 R58.2 R123.2 R219.2 R692.1 U5.7(PVIN) U5.8(AVIN) U12.3(VIN1) U12.4(VIN2) U25.7(VIN) U33.6(IN) U65.7(VIN) U72.4(IN) U103.5(VCC) U104.5(VCC) U106.1(ENABLE) U106.6(VCC) ; also on sheet 17 25
VCC3V3_SYS_PG: R580.2 R583.2 TP49.1(TP) ; also on sheet 16 17
VCC_3V3_SYS: R143.2 ; also on sheet 2 5 6 7 8 10 11 12 13 14 16 17 18 19 20 21 23 24 25 26 27 29 30 39 40
VCC_CORE: C77.1 C486.1 L4.2 TP23.1(TP) ; also on sheet 14
VCC_CORE_EN: R584.2 TP24.1(TP) U103.4(Y)
VCC_CORE_FB: C96.2 R117.2 R118.2 U25.2(FB)
VCC_CORE_PG: R123.1 U25.8(PG) U104.2(B) ; also on sheet 8 17
VDD1V8_PG: C403.1 R143.1 R581.2 TP50.1(TP) U33.5(PG) U65.2(PG) ; also on sheet 8
VDD_0V85: C33.1 TP8.1(TP) U12.8(VOUT) ; also on sheet 14
VDD_0V85_EN: R57.1 U104.4(Y)
VDD_0V85_PG: R58.1 U12.2(PG) ; also on sheet 8
VDD_CORE: C96.1 R118.1 TP14.1(TP) ; also on sheet 3 4 14 25
VDDA1V8: C129.1 R144.1 TP29.1(TP) U33.1(OUT) ; also on sheet 14
VDDAR_0V85_SENSE: R690.1 R691.1 U106.3(SENSE)
VDDAR_CORE: R44.1 TP10.1(TP) ; also on sheet 4 14
VDDR_CORE: R690.2 ; also on sheet 3 4 25
VMON_0V85: R692.2 U103.2(B) U106.4(SENSE_OUT)
VMON_0V85_CT: C535.1 U106.5(CT)
VPP_1V8: C243.1 TP52.1(TP) U72.1(OUT) ; also on sheet 4
VPP_LDO_EN: R263.2 R582.2 TP53.1(TP) ; also on sheet 13
N26735382: C202.1 U5.9(SS/TR)
N26735416: R213.1 R214.2 U5.4(FB)
N26735457: L2.1 U5.2(SW)
N26735496: L8.1 U65.6(SW)
N26735653: R144.2 R145.1 U33.2(FB)
N26736579: L4.1 U25.6(SW)
N26736751: R57.2 U12.1(EN)
N26736805: R44.2 R49.1 U12.7(FB)
N27943339: R580.1 U65.1(EN)
N27943633: R581.1 U5.6(EN)
N27943804: R582.1 U72.3(EN)
N27943890: R583.1 U33.4(EN)
N27943939: R584.1 U25.1(EN)

Not connected (* = marked no-connect by the designer): U5 10(MODE)*; U25 4(NC)*

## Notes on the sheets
sheet 15
- SoC POWER SUPPLY
- 1.8V IO, 3.0AMPS SUPPLY
- 0.75 / 0.8 /0.85V, 3.0AMPS SUPPLY
- Rfb
- CORE VOLTAGE
- Rfb RES TO BE PLACED
- 0.75V
- Rfb = 24.9K
- 1.2V, 2.0AMPS SUPPLY
- 0.80V
- Rfb = 33.2K
- 0.85V
- Rfb = 41.2K
- 0.85 V, 1.5AMPS SUPPLY
- Ren
- 1.8V VPP, 0.15AMPS SUPPLY
- If VDD_CORE = 0.75V,
  Mount Ren
  If VDD_CORE =0.85
  DNI Ren
- 1.8V Analog , 1AMPS SUPPLY
- 0.85V Voltage Monitor for Power Down Sequence
- delay = 40us by default
  CT = OPEN
- Off Page Connections
- SENSE_OUT is De-Asserted when 0.85V Falls below 0.55V
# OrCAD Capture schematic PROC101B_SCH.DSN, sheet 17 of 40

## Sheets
17 37.DUAL & PREREG REGULATOR: size C; title: DUAL & PREREG REGULATOR

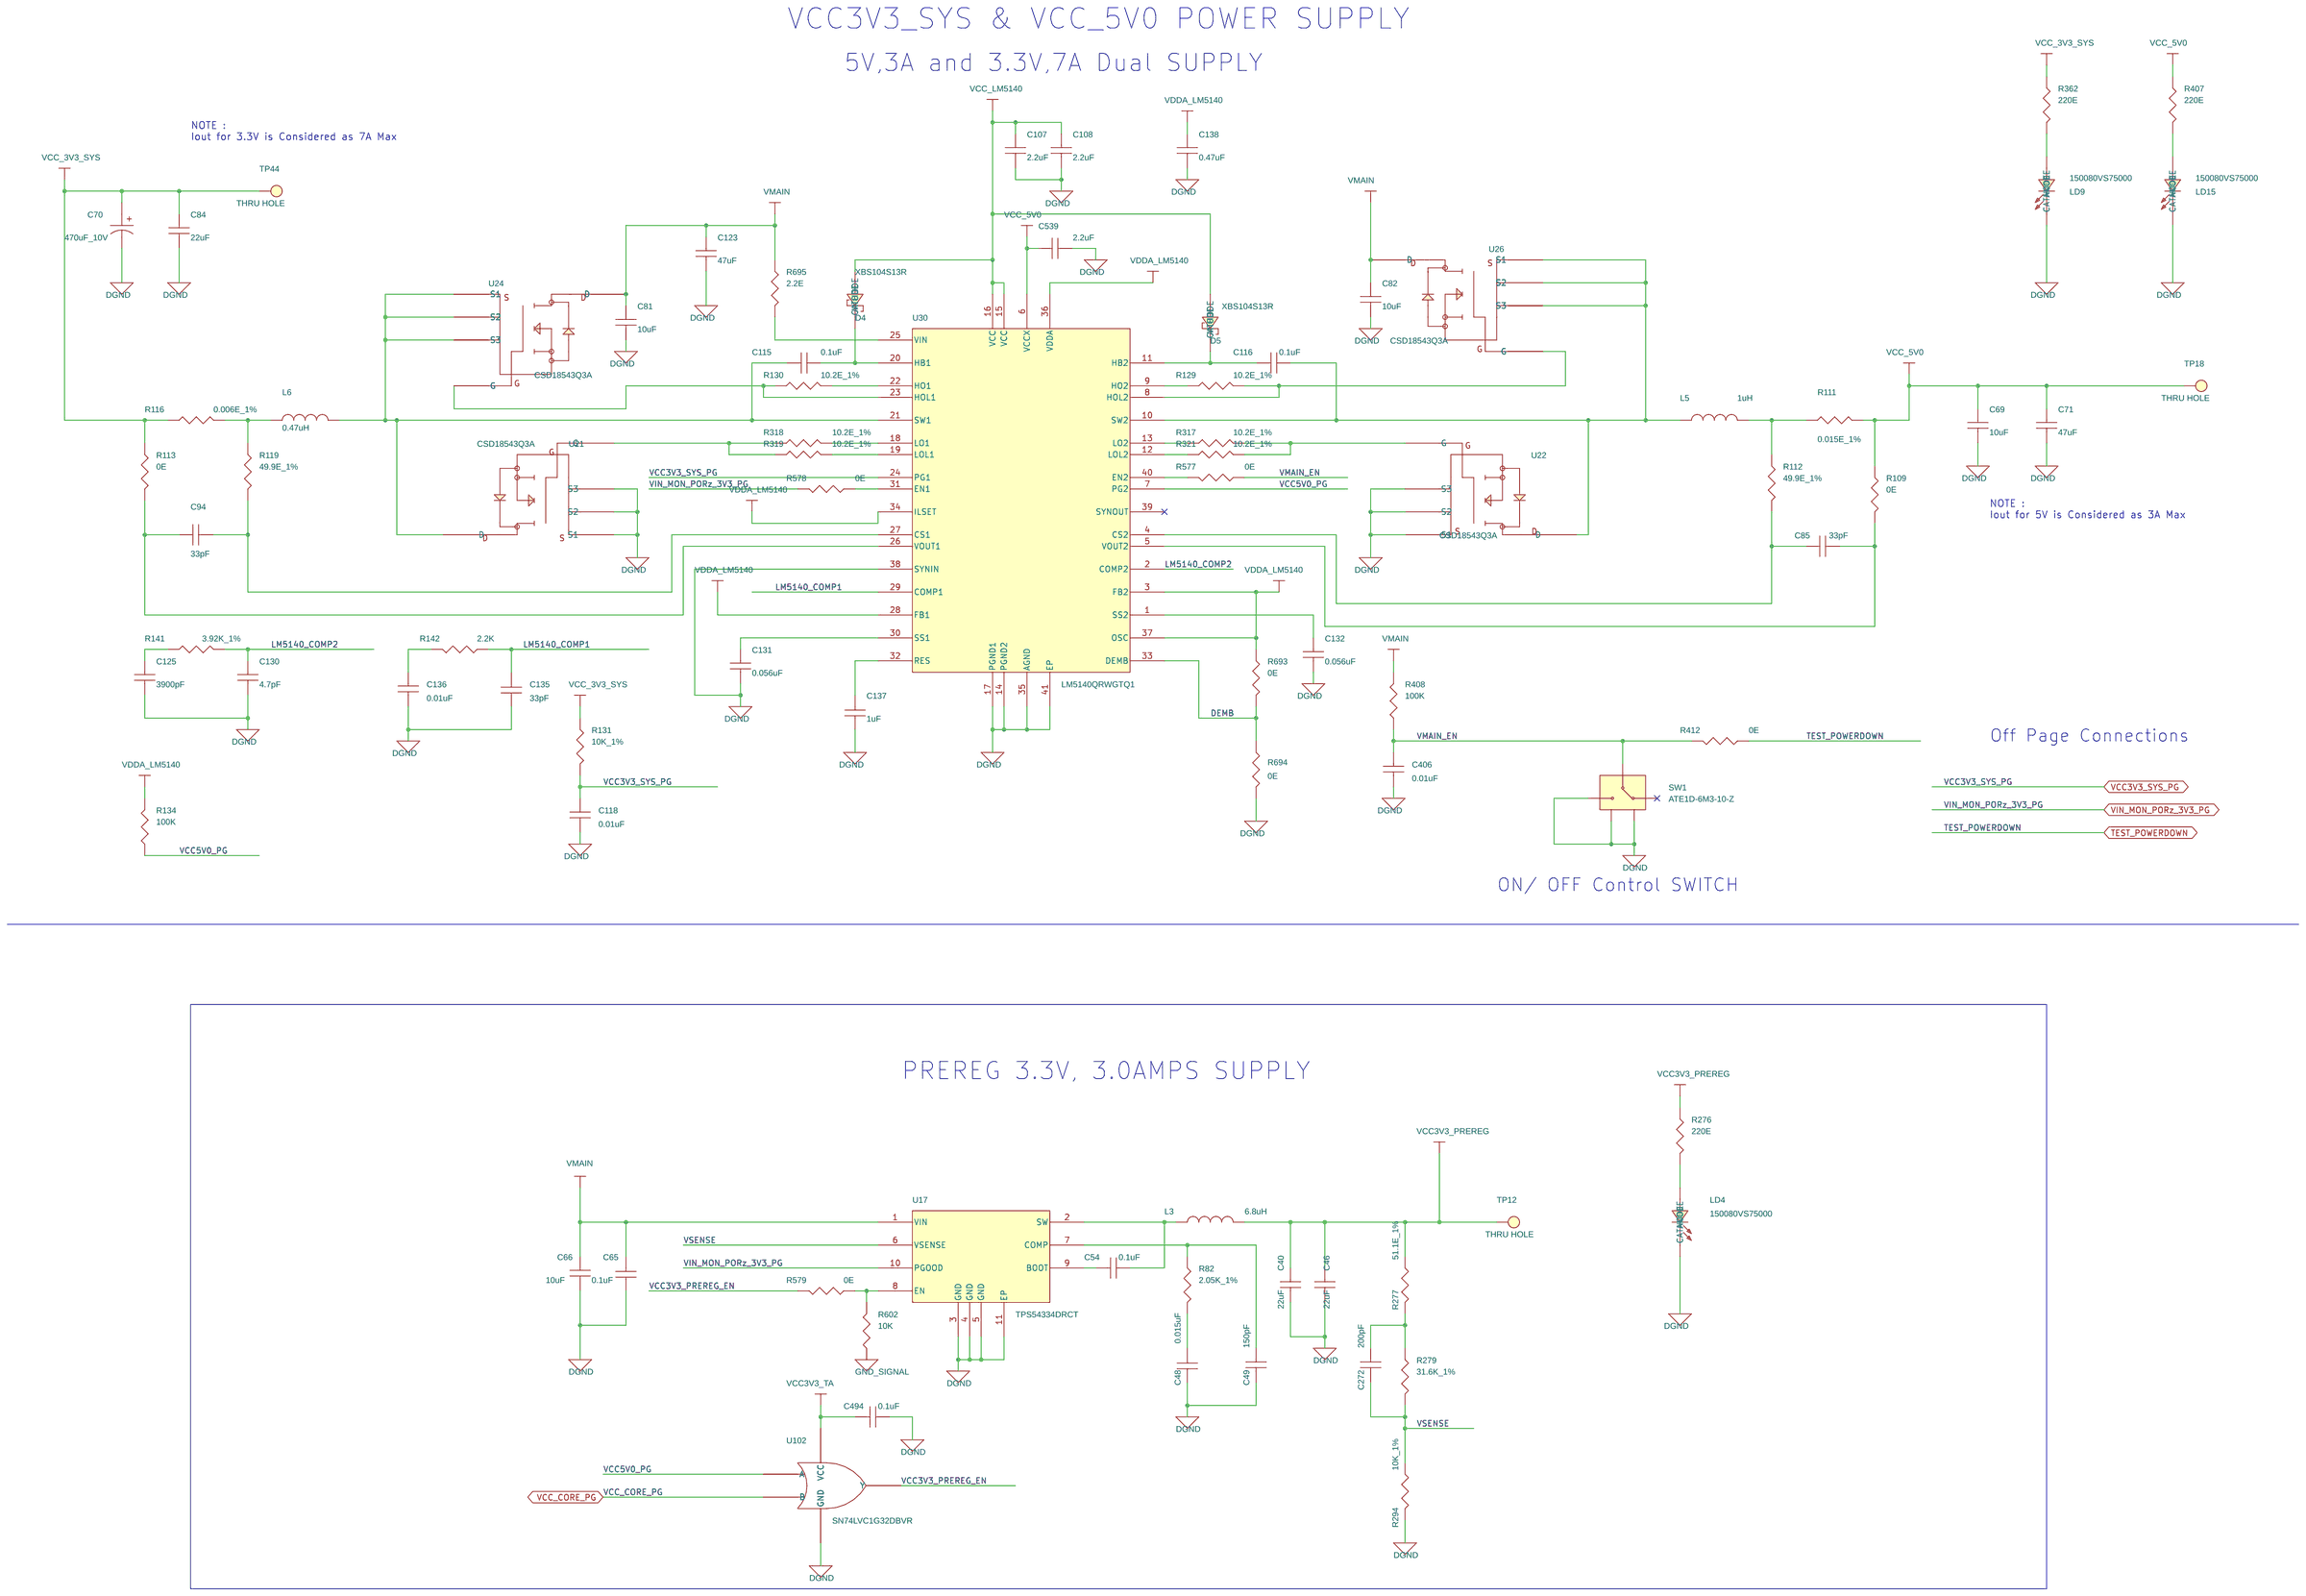
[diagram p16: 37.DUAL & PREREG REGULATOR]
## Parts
C40  22uF  [CAP0603_1]
C46  22uF  [CAP0603_1]
C48  0.015uF  [CAP0402_0-75]
C49  150pF  [CAP0402_0-75]
C54  0.1uF  [CAP0402_0-75]
C65  0.1uF  [CAP0402_0-75]
C66  10uF  [CAP0603_1]
C69  10uF  [CAP1206_2]
C70  470uF_10V  [CAPAE_875115252003_330X330_SMD_8-7]
C71  47uF  [CAP1206_2]
C81  10uF  [CAP1206_2]
C82  10uF  [CAP1206_2]
C84  22uF  [CAP1206_2]
C85  33pF  [CAP0402_0-75]
C94  33pF  [CAP0402_0-75]
C107  2.2uF  [CAP0603_1]
C108  2.2uF  [CAP0603_1]
C115  0.1uF  [CAP0402_0-75]
C116  0.1uF  [CAP0402_0-75]
C118  0.01uF  [CAP0402_0-75]
C123  47uF  [CAP1206_2]
C125  3900pF  [CAP0402_0-75]
C130  4.7pF  [CAP0402_0-75]
C131  0.056uF  [CAP0402_0-75]
C132  0.056uF  [CAP0402_0-75]
C135  33pF  [CAP0402_0-75]
C136  0.01uF  [CAP0402_0-75]
C137  1uF  [CAP0402_0-75]
C138  0.47uF  [CAP0603_1]
C272  200pF  [CAP0402_0-75]
C406  0.01uF  [CAP0402_0-75]
C494  0.1uF  [CAP0402_0-75]
C539  2.2uF  [CAP0603_1]
D4  XBS104S13R  [DIO_SOD323_1]
D5  XBS104S13R  [DIO_SOD323_1]
L3  6.8uH  [IND_74439346068_260X270_SMD_6-1]
L5  1uH  [IND_744316100_230X220_SMD_4-3]
L6  0.47uH  [IND_744373460047_270X270_SMD_3]
LD4  150080VS75000  [LED_150080VS75000_80X50_SMD_0-8]
LD9  150080VS75000  [LED_150080VS75000_80X50_SMD_0-8]
LD15  150080VS75000  [LED_150080VS75000_80X50_SMD_0-8]
R82  2.05K_1%  [RES0402_0-5]
R109  0E  [RES0402_0-5]
R111  0.015E_1%  [RES1206_1]
R112  49.9E_1%  [RES0402_0-5]
R113  0E  [RES0402_0-5]
R116  0.006E_1%  [RES1206_0-75]
R119  49.9E_1%  [RES0402_0-5]
R129  10.2E_1%  [RES0402_0-5]
R130  10.2E_1%  [RES0402_0-5]
R131  10K_1%  [RES0402_0-5]
R134  100K  [RES0402_0-5]
R141  3.92K_1%  [RES0402_0-5]
R142  2.2K  [RES0402_0-5]
R276  220E  [RES0402_0-5]
R277  51.1E_1%  [RES0402_0-5]
R279  31.6K_1%  [RES0402_0-5]
R294  10K_1%  [RES0402_0-5]
R317  10.2E_1%  [RES0402_0-5]
R318  10.2E_1%  [RES0402_0-5]
R319  10.2E_1%  [RES0402_0-5]
R321  10.2E_1%  [RES0402_0-5]
R362  220E  [RES0402_0-5]
R407  220E  [RES0402_0-5]
R408  100K  [RES0402_0-5]
R412  0E  [RES0402_0-5]
R577  0E  [RES0402_0-5]
R578  0E  [RES0402_0-5]
R579  0E  [RES0402_0-5]
R602  10K  [RES0402_0-5]
R693  0E  [RES0402_0-5]
R694  0E  [RES0402_0-5]
R695  2.2E  [RES0603_0-75]
SW1  ATE1D-6M3-10-Z  [SW3_ATE1F-6M3_370X710_TH_5-6]
TP12  THRU HOLE  [TP_40X65]
TP18  THRU HOLE  [TP_40X65]
TP44  THRU HOLE  [TP_40X65]
U17  TPS54334DRCT  [SON10_19-68_125X125_1]
U21  CSD18543Q3A  [VSONP8_CSD18543Q_120X130_0-9]
U22  CSD18543Q3A  [VSONP8_CSD18543Q_120X130_0-9]
U24  CSD18543Q3A  [VSONP8_CSD18543Q_120X130_0-9]
U26  CSD18543Q3A  [VSONP8_CSD18543Q_120X130_0-9]
U30  LM5140QRWGTQ1  [QFN40_19-68_240X240_0-9_EP3-4]
U102  SN74LVC1G32DBVR  [SOT23-5_1-5]

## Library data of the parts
C40 C46 = CAP: CAP CERAMIC 22uF 6.3V 20% X5R 0603; Chkd/date: JEBRAN/090915; Crtd /date: JEBRAN/090915; Custom_Duty: 15%; Customs_HS_Code: 85322990; Distributor_name: DIGIKEY; Distributor_part_number: 490-7611-2-ND; Footprint Path: Y:\MIS_DATABASE\Library\ALTIUM_TOOL\PCB_FOOTPRINTS\Altium_Footprint_Lib.PcbLib; Height: 1.00MM; Library Path: Y:\MIS_DATABASE\Library\ALTIUM_TOOL\SCHEMATICS_PARTS\MS_DISCRETE_Library.schlib; Mfr_name: MURATA; Mfr_part_number: GRM188R60J226MEA0; Mistral Part No: 120015090007-R; Package: 0603; Part_type: CAPACITORS\CERAMIC; Project: OCTBTS_3000; RoHS: RoHS; Temperature: -55°C+85°C; Tolerance: 20%; Voltage: 6.3V; Wattage: NA; Weight: 6.3mg; Datasheet: Y:\MIS_DATABASE\DATASHEETS\CAPACITORS\MURATA-GXX-SER_NOV17.PDF
C48 = CAP: CAP CERAMIC 0.015uF 25V 10% X7R 0402; Chkd/date: MANIRAJA/170820; Crtd /date: ALVY/170820; Custom_Duty: 15%; Customs_HS_Code: 85322990; Distributor_name: DIGIKEY; Distributor_part_number: 732-7546-1-ND; Footprint Path: Y:\MIS_DATABASE\Library\ALTIUM_TOOL\PCB_FOOTPRINTS\Altium_Footprint_Lib.PcbLib; Height: 0.55MM; Library Path: Y:\MIS_DATABASE\Library\ALTIUM_TOOL\SCHEMATICS_PARTS\MS_DISCRETE_Library.schlib; Mfr_name: WURTH ELECTRONICS; Mfr_part_number: 885012205051; Mistral Part No: 120020080005-R; Package: 0402; Part_type: CAPACITORS\CERAMIC; Project: AM64x_EVM_BRD; RoHS: RoHS; Temperature: -55°C+125°C; Tolerance: 10%; Voltage: 25V; Wattage: NA; Weight: 0.65mg; Datasheet: Y:\MIS_DATABASE\DATASHEETS\CAPACITORS\885012205051.PDF
C49 = CAP: CAP CERAMIC 150pF 50V 10% X7R 0402; Chkd/date: MANIRAJA/240118; Crtd /date: MANIRAJA/240118; Custom_Duty: 15%; Customs_HS_Code: 85322990; Distributor_name: DIGIKEY; Distributor_part_number: 732-7551-1-ND; Footprint Path: Y:\MIS_DATABASE\Library\ALTIUM_TOOL\PCB_FOOTPRINTS\Altium_Footprint_Lib.PcbLib; Height: 0.55MM; Library Path: Y:\MIS_DATABASE\Library\ALTIUM_TOOL\SCHEMATICS_PARTS\MS_DISCRETE_Library.schlib; Mfr_name: WURTH ELECTRONICS; Mfr_part_number: 885012205056; Mistral Part No: 120018010022-R; Package: 0402; Part_type: CAPACITORS\CERAMIC; Project: TI_MAXIE_CPB; RoHS: RoHS; Temperature: -55°C+125°C; Tolerance: 10%; Voltage: 50V; Wattage: NA; Weight: 0.65mg; Datasheet: Y:\MIS_DATABASE\DATASHEETS\CAPACITORS\885012205056.PDF
C54 C65 C115 C116 C494 = CAP: CAP CERAMIC 0.1uF 25V 20% X5R 0402; Alt_Mfr_name: YAGEO AMERICA; Alt_Mfr_part_number: CC0402KRX5R8BB104; Chkd/date: MANIRAJA/170820; Crtd /date: ALVY/170820; Custom_Duty: 15%; Customs_HS_Code: 85322990; Distributor_name: DIGIKEY; Distributor_part_number: 732-7495-1-ND; Footprint Path: Y:\MIS_DATABASE\Library\ALTIUM_TOOL\PCB_FOOTPRINTS\Altium_Footprint_Lib.PcbLib; Height: 0.55MM; Library Path: Y:\MIS_DATABASE\Library\ALTIUM_TOOL\SCHEMATICS_PARTS\MS_DISCRETE_Library.schlib; Mfr_name: WURTH ELECTRONICS; Mfr_part_number: 885012105018; Mistral Part No: 120020080003-R; Package: 0402; Part_type: CAPACITORS\CERAMIC; Project: AM64x_EVM_BRD; RoHS: RoHS; Temperature: -55°C+85°C; Tolerance: 20%; Voltage: 25V; Wattage: NA; Weight: 0.65mg; Datasheet: Y:\MIS_DATABASE\DATASHEETS\CAPACITORS\885012105018.PDF
C66 = CAP: CAP CERAMIC 10uF 35V 20% X5R 0603; Chkd/date: MANIRAJA/170519; Crtd /date: ALVY/160519; Custom_Duty: 15%; Customs_HS_Code: 85322990; Distributor_name: DIGIKEY; Distributor_part_number: 490-13248-1-ND; Footprint Path: Y:\MIS_DATABASE\Library\ALTIUM_TOOL\PCB_FOOTPRINTS\Altium_Footprint_Lib.PcbLib; Height: 1.00MM; Library Path: Y:\MIS_DATABASE\Library\ALTIUM_TOOL\SCHEMATICS_PARTS\MS_DISCRETE_Library.schlib; Mfr_name: MURATA; Mfr_part_number: GRM188R6YA106MA73D; Mistral Part No: 120019050016-R; Package: 0603; Part_type: CAPACITORS\CERAMIC; Project: BRUKER_SD820_COMMONDO; RoHS: RoHS; Temperature: -55°C+85°C; Tolerance: 20%; Voltage: 35V; Wattage: NA; Weight: 9mg; Datasheet: Y:\MIS_DATABASE\DATASHEETS\CAPACITORS\GRM188R6YA106MA73.PDF
C69 = CAP: CAP CERAMIC 10uF 25V 10% X5R 1206; Chkd/date: VASANTHA/10115; Crtd /date: VASANTHA/10115; Custom_Duty: 15%; Customs_HS_Code: 85322990; Distributor_name: DIGIKEY; Distributor_part_number: 490-3373-1-ND; Footprint Path: Y:\MIS_DATABASE\Library\ALTIUM_TOOL\PCB_FOOTPRINTS\Altium_Footprint_Lib.PcbLib; Height: 1.80MM; Library Path: Y:\MIS_DATABASE\Library\ALTIUM_TOOL\SCHEMATICS_PARTS\MS_DISCRETE_Library.schlib; Mfr_name: MURATA; Mfr_part_number: GRM31CR61E106KA12L; Mistral Part No: 120015110014-R; Package: 1206; Part_type: CAPACITORS\CERAMIC; Project: OCTASIC_3600; RoHS: RoHS; Temperature: -55°C+85°C; Tolerance: 10%; Voltage: 25V; Wattage: NA; Weight: 40mg; Datasheet: Y:\MIS_DATABASE\DATASHEETS\CAPACITORS\MURATA-GXX-SER_NOV17.PDF
C70 = CAP_POL: CAP POLYMER 470uF 10V 20% SMD; Chkd/date: MANIRAJA/140820; Crtd /date: ALVY/140820; Custom_Duty: 15%; Customs_HS_Code: 85322990; Distributor_name: DIGIKEY; Distributor_part_number: 732-6451-1-ND; Footprint Path: Y:\MIS_DATABASE\Library\ALTIUM_TOOL\PCB_FOOTPRINTS\Altium_Footprint_Lib.PcbLib; Height: 8.70MM; Library Path: Y:\MIS_DATABASE\Library\ALTIUM_TOOL\SCHEMATICS_PARTS\MS_DISCRETE_Library.schlib; Mfr_name: WURTH ELECTRONICS; Mfr_part_number: 875115252003; Mistral Part No: 120020080001-R; Package: SMD; Part_type: CAPACITORS\POLYPROPYLENE; Project: AM64x_EVM_BRD; RoHS: RoHS; Temperature: -55°C+105°C; Tolerance: 20%; Voltage: 10V; Wattage: NA; Weight: 640.2mg; Datasheet: Y:\MIS_DATABASE\DATASHEETS\CAPACITORS\875115252003.PDF
C71 C123 = CAP: CAP CERAMIC 47uF 25V 20% X5R 1206; Chkd/date: MANIRAJA/230118; Crtd /date: MANIRAJA/230118; Custom_Duty: 15%; Customs_HS_Code: 85322990; Distributor_name: DIGIKEY; Distributor_part_number: 490-16268-1-ND; Footprint Path: Y:\MIS_DATABASE\Library\ALTIUM_TOOL\PCB_FOOTPRINTS\Altium_Footprint_Lib.PcbLib; Height: 1.80MM; Library Path: Y:\MIS_DATABASE\Library\ALTIUM_TOOL\SCHEMATICS_PARTS\MS_DISCRETE_Library.schlib; Mfr_name: MURATA; Mfr_part_number: GRM31CR61E476ME44L; Mistral Part No: 120013050002-R; Package: 1206; Part_type: CAPACITORS\CERAMIC; Project: TI_MAXIE_CPB; RoHS: RoHS; Temperature: -55°C+85°C; Tolerance: 20%; Voltage: 25V; Wattage: NA; Weight: 40mg; Datasheet: Y:\MIS_DATABASE\DATASHEETS\CAPACITORS\MURATA-GXX-SER_NOV17.PDF
C81 C82 = CAP: CAP CERAMIC 10uF 50V 20% X5R 1206; Chkd/date: MANIRAJA/240118; Crtd /date: MANIRAJA/240118; Custom_Duty: 15%; Customs_HS_Code: 85322990; Distributor_name: DIGIKEY; Distributor_part_number: 490-10756-1-ND; Footprint Path: Y:\MIS_DATABASE\Library\ALTIUM_TOOL\PCB_FOOTPRINTS\Altium_Footprint_Lib.PcbLib; Height: 1.80MM; Library Path: Y:\MIS_DATABASE\Library\ALTIUM_TOOL\SCHEMATICS_PARTS\MS_DISCRETE_Library.schlib; Mfr_name: MURATA; Mfr_part_number: GRM31CR61H106MA12L; Mistral Part No: 120018010013-R; Package: 1206; Part_type: CAPACITORS\CERAMIC; Project: TI_MAXIE_CPB; RoHS: RoHS; Temperature: -55°C+85°C; Tolerance: 20%; Voltage: 50V; Wattage: NA; Weight: 40mg; Datasheet: Y:\MIS_DATABASE\DATASHEETS\CAPACITORS\GRM31CR61H106MA12.PDF
C84 = CAP: CAP CERAMIC 22uF 25V 20% X5R 1206; Chkd/date: MANIRAJA/030419; Crtd /date: MANIRAJA/030419; Custom_Duty: 15%; Customs_HS_Code: 85322990; Distributor_name: DIGIKEY; Distributor_part_number: 490-10755-1-ND; Footprint Path: Y:\MIS_DATABASE\Library\ALTIUM_TOOL\PCB_FOOTPRINTS\Altium_Footprint_Lib.PcbLib; Height: 1.80MM; Library Path: Y:\MIS_DATABASE\Library\ALTIUM_TOOL\SCHEMATICS_PARTS\MS_DISCRETE_Library.schlib; Mfr_name: MURATA; Mfr_part_number: GRM31CR61E226ME15L; Mistral Part No: 120015080009-R; Package: 1206; Part_type: CAPACITORS\CERAMIC; Project: OCTASIC_3000; RoHS: RoHS; Temperature: -55°C+85°C; Tolerance: 20%; Voltage: 25V; Wattage: NA; Weight: 16.2mg; Datasheet: Y:\MIS_DATABASE\DATASHEETS\CAPACITORS\GRM31CR61E226ME15.PDF
C85 C94 C135 = CAP: CAP CERAMIC 33pF 50V 5% C0G(NP0) 0402; Chkd/date: MANIRAJA/170820; Crtd /date: ALVY/170820; Custom_Duty: 15%; Customs_HS_Code: 85322990; Distributor_name: DIGIKEY; Distributor_part_number: 732-7472-1-ND; Footprint Path: Y:\MIS_DATABASE\Library\ALTIUM_TOOL\PCB_FOOTPRINTS\Altium_Footprint_Lib.PcbLib; Height: 0.55MM; Library Path: Y:\MIS_DATABASE\Library\ALTIUM_TOOL\SCHEMATICS_PARTS\MS_DISCRETE_Library.schlib; Mfr_name: WURTH ELECTRONICS; Mfr_part_number: 885012005058; Mistral Part No: 120009030395-R; Package: 0402; Part_type: CAPACITORS\CERAMIC; Project: AM64x_EVM_BRD; RoHS: RoHS; Temperature: -55°C+125°C; Tolerance: 5%; Voltage: 50V; Wattage: NA; Weight: 0.65mg; Datasheet: Y:\MIS_DATABASE\DATASHEETS\CAPACITORS\885012005058.PDF
C107 C108 C539 = CAP: CAP CERAMIC 2.2uF 35V 10% X5R 0603; Chkd/date: VASANTHA/270117; Crtd /date: MANIRAJA/270117; Custom_Duty: 15%; Customs_HS_Code: 85322990; Distributor_name: DIGIKEY; Distributor_part_number: 490-7204-1-ND; Footprint Path: Y:\MIS_DATABASE\Library\ALTIUM_TOOL\PCB_FOOTPRINTS\Altium_Footprint_Lib.PcbLib; Height: 0.90MM; Library Path: Y:\MIS_DATABASE\Library\ALTIUM_TOOL\SCHEMATICS_PARTS\MS_DISCRETE_Library.schlib; Mfr_name: MURATA; Mfr_part_number: GRM188R6YA225KA12D; Mistral Part No: 120017010016-R; Package: 0603; Part_type: CAPACITORS\CERAMIC; Project: SD820_NANO_SOM; RoHS: RoHS; Temperature: -55°C+85°C; Tolerance: 10%; Voltage: 35V; Wattage: NA; Weight: 6.3mg; Datasheet: Y:\MIS_DATABASE\DATASHEETS\CAPACITORS\MURATA-GXX-SER_NOV17.PDF
C118 C136 C406 = CAP: CAP CERAMIC 0.01uF 25V 10% X7R 0402; Chkd/date: MANIRAJA/170820; Crtd /date: ALVY/170820; Custom_Duty: 15%; Customs_HS_Code: 85322990; Distributor_name: DIGIKEY; Distributor_part_number: 732-7545-1-ND; Footprint Path: Y:\MIS_DATABASE\Library\ALTIUM_TOOL\PCB_FOOTPRINTS\Altium_Footprint_Lib.PcbLib; Height: 0.55MM; Library Path: Y:\MIS_DATABASE\Library\ALTIUM_TOOL\SCHEMATICS_PARTS\MS_DISCRETE_Library.schlib; Mfr_name: WURTH ELECTRONICS; Mfr_part_number: 885012205050; Mistral Part No: 120011090040-R; Package: 0402; Part_type: CAPACITORS\CERAMIC; Project: AM64x_EVM_BRD; RoHS: RoHS; Temperature: -55°C+125°C; Tolerance: 10%; Voltage: 25V; Wattage: NA; Weight: 0.65mg; Datasheet: Y:\MIS_DATABASE\DATASHEETS\CAPACITORS\885012205050.PDF
C125 = CAP: CAP CERAMIC 3900pF 25V 10% X7R 0402; Chkd/date: VASANTHA/211215; Crtd /date: VASANTHA/211215; Custom_Duty: 15%; Customs_HS_Code: 85322990; Distributor_name: DIGIKEY; Distributor_part_number: 311-1038-1-ND; Footprint Path: Y:\MIS_DATABASE\Library\ALTIUM_TOOL\PCB_FOOTPRINTS\Altium_Footprint_Lib.PcbLib; Height: 0.55MM; Library Path: Y:\MIS_DATABASE\Library\ALTIUM_TOOL\SCHEMATICS_PARTS\MS_DISCRETE_Library.schlib; Mfr_name: YAGEO AMERICA; Mfr_part_number: CC0402KRX7R8BB392; Mistral Part No: 120015120019-R; Package: 0402; Part_type: CAPACITORS\CERAMIC; Project: DLRL_NBSDR; RoHS: RoHS; Temperature: -55°C+125°C; Tolerance: 10%; Voltage: 25V; Wattage: NA; Weight: 0.65mg; Datasheet: Y:\MIS_DATABASE\DATASHEETS\CAPACITORS\YACC-X7R.PDF
C130 = CAP: CAP CERAMIC 4.7pF 50V 0.25pF HI-Q C0G(NP0) 0402; Chkd/date: VASANTHA/220814; Crtd /date: USMAN/290413; Custom_Duty: 15%; Customs_HS_Code: 85322990; Distributor_name: DIGIKEY; Distributor_part_number: 490-3100-1-ND; Footprint Path: Y:\MIS_DATABASE\Library\ALTIUM_TOOL\PCB_FOOTPRINTS\Altium_Footprint_Lib.PcbLib; Height: 0.55MM; Library Path: Y:\MIS_DATABASE\Library\ALTIUM_TOOL\SCHEMATICS_PARTS\MS_DISCRETE_Library.schlib; Mfr_name: MURATA; Mfr_part_number: GJM1555C1H4R7CB01D; Mistral Part No: 120013040025-R; Package: 0402; Part_type: CAPACITORS\CERAMIC; Project: DTRM; RoHS: RoHS; Temperature: -55°C+125°C; Tolerance: 0.25pF%; Voltage: 50V; Wattage: NA; Weight: 6mg; Datasheet: Y:\MIS_DATABASE\DATASHEETS\CAPACITORS\MURATA-GXX-SER_NOV17.PDF
C131 C132 = CAP: CAP CERAMIC 0.056uF 10V 10% X7R 0402; Chkd/date: USMAN/161111; Crtd /date: CHAITHANYA/151111; Custom_Duty: 15%; Customs_HS_Code: 85322990; Distributor_name: DIGIKEY; Distributor_part_number: 399-4902-1-ND; Footprint Path: Y:\MIS_DATABASE\Library\ALTIUM_TOOL\PCB_FOOTPRINTS\Altium_Footprint_Lib.PcbLib; Height: 0.55MM; Library Path: Y:\MIS_DATABASE\Library\ALTIUM_TOOL\SCHEMATICS_PARTS\MS_DISCRETE_Library.schlib; Mfr_name: KEMET; Mfr_part_number: C0402C563K8RACTU; Mistral Part No: 120011110014-R; Package: 0402; Part_type: CAPACITORS\CERAMIC; Project: AVCDP1; RoHS: RoHS; Temperature: -55°C+125°C; Tolerance: 10%; Voltage: 10V; Wattage: NA; Weight: 0.65mg; Datasheet: Y:\MIS_DATABASE\DATASHEETS\CAPACITORS\KEMET-C-X7R.PDF
C137 = CAP: CAP CERAMIC 1uF 10V 20% X5R 0402; Chkd/date: MANIRAJA/210820; Crtd /date: ALVY/190820; Custom_Duty: 15%; Customs_HS_Code: 85322990; Distributor_name: DIGIKEY; Distributor_part_number: 732-7489-1-ND; Footprint Path: Y:\MIS_DATABASE\Library\ALTIUM_TOOL\PCB_FOOTPRINTS\Altium_Footprint_Lib.PcbLib; Height: 0.55MM; Library Path: Y:\MIS_DATABASE\Library\ALTIUM_TOOL\SCHEMATICS_PARTS\MS_DISCRETE_Library.schlib; Mfr_name: WURTH ELECTRONICS; Mfr_part_number: 885012105012; Mistral Part No: 120020080009-R; Package: 0402; Part_type: CAPACITORS\CERAMIC; Project: AM64x_EVM_BRD; RoHS: RoHS; Temperature: -55°C+85°C; Tolerance: 20%; Voltage: 10V; Wattage: NA; Weight: 0.65mg; Datasheet: Y:\MIS_DATABASE\DATASHEETS\CAPACITORS\885012105012.PDF
C138 = CAP: CAP CERAMIC 0.47uF 25V 10% X7R 0603; Chkd/date: MANIRAJA/170820; Crtd /date: ALVY/170820; Custom_Duty: 15%; Customs_HS_Code: 85322990; Distributor_name: DIGIKEY; Distributor_part_number: 732-7993-1-ND; Footprint Path: Y:\MIS_DATABASE\Library\ALTIUM_TOOL\PCB_FOOTPRINTS\Altium_Footprint_Lib.PcbLib; Height: 0.95MM; Library Path: Y:\MIS_DATABASE\Library\ALTIUM_TOOL\SCHEMATICS_PARTS\MS_DISCRETE_Library.schlib; Mfr_name: WURTH ELECTRONICS; Mfr_part_number: 885012206075; Mistral Part No: 120009030111-R; Package: 0603; Part_type: CAPACITORS\CERAMIC; Project: AM64x_EVM_BRD; RoHS: RoHS; Temperature: -55°C+125°C; Tolerance: 10%; Voltage: 25V; Wattage: NA; Weight: 35mg; Datasheet: Y:\MIS_DATABASE\DATASHEETS\CAPACITORS\885012206075.PDF
C272 = CAP: CAP CERAMIC 200pF 50V 5% C0G(NP0) AUTO 0402; Chkd/date: MANIRAJA/070220; Crtd /date: ALVY/070220; Custom_Duty: 15%; Customs_HS_Code: 85322990; Distributor_name: DIGIKEY; Distributor_part_number: GCM1555C1H201JA16D-ND; Footprint Path: Y:\MIS_DATABASE\Library\ALTIUM_TOOL\PCB_FOOTPRINTS\Altium_Footprint_Lib.PcbLib; Height: 0.55MM; Library Path: Y:\MIS_DATABASE\Library\ALTIUM_TOOL\SCHEMATICS_PARTS\MS_DISCRETE_Library.schlib; Mfr_name: MURATA; Mfr_part_number: GCM1555C1H201JA16D; Mistral Part No: 120020020002-R; Package: 0402; Part_type: CAPACITORS\CERAMIC; Project: TI_MAXIE_CPB; RoHS: RoHS; Temperature: -55°C+125°C; Tolerance: 5%; Voltage: 50V; Wattage: NA; Weight: 6mg; Datasheet: Y:\MIS_DATABASE\DATASHEETS\CAPACITORS\GCM1555C1H201JA16D.PDF
D4 D5 = DIODE_SCHOTTKY: DIODE SCHOTTKY 40V 1A SOD323A; Chkd/date: MANIRAJA/150218; Crtd /date: ALVY/150218; Custom_Duty: 24%; Customs_HS_Code: 85437099; Distributor_name: DIGIKEY; Distributor_part_number: 893-1188-1-ND; Footprint Path: Y:\MIS_DATABASE\Library\ALTIUM_TOOL\PCB_FOOTPRINTS\Altium_Footprint_Lib.PcbLib; Height: 1.00MM; Library Path: Y:\MIS_DATABASE\Library\ALTIUM_TOOL\SCHEMATICS_PARTS\MS_DISCRETE_Library.schlib; Mfr_name: TOREX; Mfr_part_number: XBS104S13R-G; Mistral Part No: 130018020038-R; Package: SOD323; Part_type: DIODE\SCHOTTKY; Project: TI_MAXIE_CPB; RoHS: RoHS; Temperature: NA; Tolerance: NA; Voltage: 40V; Wattage: NA; Weight: NA; Datasheet: Y:\MIS_DATABASE\DATASHEETS\DISCRETES\DIODES\XBS104S13R-G.PDF
L3 = INDUCTOR: IND POWER 6.8uH 6.5A 20% SMD; Chkd/date: MANIRAJA/171017; Crtd /date: MANIRAJA/171017; Custom_Duty: 24%; Customs_HS_Code: 85437099; Distributor_name: DIGIKEY; Distributor_part_number: 732-10705-1-ND; Height: 6.10MM; Mfr_name: WURTH ELECTRONICS; Mfr_part_number: 74439346068; Mistral Part No: 130017100019-R; Package: SMD; Project: TI_MAXIE_CPB; RoHS: RoHS; Temperature: -40°C+125°C; Tolerance: 20%; Voltage: NA; Wattage: NA; Weight: NA; Datasheet: Y:\MIS_DATABASE\DATASHEETS\DISCRETES\INDUCTORS\74439346068.PDF
L5 = INDUCTOR: IND HI-CURRENT 1uH 11.5A 20% SMD; Chkd/date: MANIRAJA/280520; Crtd /date: ALVY/280520; Custom_Duty: 24%; Customs_HS_Code: 85437099; Distributor_name: DIGIKEY; Distributor_part_number: 732-6176-1-ND; Footprint Path: Y:\MIS_DATABASE\Library\ALTIUM_TOOL\PCB_FOOTPRINTS\Altium_Footprint_Lib.PcbLib; Height: 4.30MM; Library Path: Y:\MIS_DATABASE\Library\ALTIUM_TOOL\SCHEMATICS_PARTS\MS_DISCRETE_Library.schlib; Mfr_name: WURTH ELECTRONICS; Mfr_part_number: 744316100; Mistral Part No: 130020050041-R; Package: SMD; Project: AM64x-GP_EVM BRD; RoHS: RoHS; Temperature: -40°C+150°C; Tolerance: 20%; Voltage: NA; Wattage: NA; Weight: 570mg; Datasheet: Y:\MIS_DATABASE\DATASHEETS\DISCRETES\INDUCTORS\744316100.PDF
L6 = INDUCTOR: IND POWER 0.47uH 11.5A 20% SMD; Chkd/date: MANIRAJA/130820; Crtd /date: ALVY/130820; Custom_Duty: 24%; Customs_HS_Code: 85437099; Distributor_name: DIGIKEY; Distributor_part_number: 732-3366-1-ND; Footprint Path: Y:\MIS_DATABASE\Library\ALTIUM_TOOL\PCB_FOOTPRINTS\Altium_Footprint_Lib.PcbLib; Height: 3.00MM; Library Path: Y:\MIS_DATABASE\Library\ALTIUM_TOOL\SCHEMATICS_PARTS\MS_DISCRETE_Library.schlib; Mfr_name: WURTH ELECTRONICS; Mfr_part_number: 744373460047; Mistral Part No: 130020080011-R; Package: SMD; Project: AM64x_EVM_BRD; RoHS: RoHS; Temperature: -40°C+125°C; Tolerance: 20%; Voltage: NA; Wattage: NA; Weight: 719mg; Datasheet: Y:\MIS_DATABASE\DATASHEETS\DISCRETES\INDUCTORS\744373460047.PDF
LD4 LD9 LD15 = DIODE_LED: DIODE LED BRIGHT GREEN SMD; Chkd/date: MANIRAJA/180820; Crtd /date: ALVY/180820; Custom_Duty: 24%; Customs_HS_Code: 85439000; Distributor_name: DIGIKEY; Distributor_part_number: 732-4986-1-ND; Footprint Path: Y:\MIS_DATABASE\Library\ALTIUM_TOOL\PCB_FOOTPRINTS\Altium_Footprint_Lib.PcbLib; Height: 0.80MM; Library Path: Y:\MIS_DATABASE\Library\ALTIUM_TOOL\SCHEMATICS_PARTS\MS_OPTO_Library.schlib; Mfr_name: WURTH ELECTRONICS; Mistral Part No: 130020080012-R; Package: SMD; Part_type: OPTO\LED; Project: AM64x_EVM_BRD; RoHS: RoHS; Temperature: -40°C+85°C; Tolerance: NA; Voltage: NA; Wattage: NA; Weight: 10mg; Datasheet: Y:\MIS_DATABASE\DATASHEETS\DISCRETES\LEDS\150080VS75000.PDF
R82 = RESISTOR: RES 2.05K 1/10W 1% 0402; Chkd/date: NAVEED/261214; Crtd /date: JEBRAN/271114; Custom_Duty: 15%; Customs_HS_Code: 85332119; Distributor_name: DIGIKEY; Distributor_part_number: P2.05KLCT-ND; Footprint Path: Y:\MIS_DATABASE\Library\ALTIUM_TOOL\PCB_FOOTPRINTS\Altium_Footprint_Lib.PcbLib; Height: 0.40MM; Library Path: Y:\MIS_DATABASE\Library\ALTIUM_TOOL\SCHEMATICS_PARTS\MS_DISCRETE_Library.schlib; Mfr_name: PANASONIC-ECG; Mfr_part_number: ERJ-2RKF2051X; Mistral Part No: 110014110019-R; Package: 0402; Part_type: RESISTORS\FIXED; Project: ZK BIOMETRIC; RoHS: RoHS; Temperature: -55°C+155°C; Tolerance: 1%; Voltage: NA; Wattage: 1/10W; Weight: 0.8mg; Datasheet: Y:\MIS_DATABASE\DATASHEETS\RESISTORS\PAN-ERJSER_NOV17.PDF
R109 R113 R412 R577-R579 R693 R694 = RESISTOR: RES 0E 1/16W JUMPER 0402; Chkd/date: VASANTHA/201216; Crtd /date: MUDDU/190810; Custom_Duty: 15%; Customs_HS_Code: 85332119; Distributor_name: DIGIKEY; Distributor_part_number: 541-0.0JCT-ND; Footprint Path: Y:\MIS_DATABASE\Library\ALTIUM_TOOL\PCB_FOOTPRINTS\Altium_Footprint_Lib.PcbLib; Height: 0.40MM; Library Path: Y:\MIS_DATABASE\Library\ALTIUM_TOOL\SCHEMATICS_PARTS\MS_DISCRETE_Library.schlib; Mfr_name: VISHAY; Mfr_part_number: CRCW04020000Z0ED; Mistral Part No: 110010080019-R; Package: 0402; Part_type: RESISTORS\FIXED; Project: PB_BUGBASE; RoHS: RoHS; Temperature: -55°C+155°C; Tolerance: NA; Voltage: NA; Wattage: 1/16W; Weight: 0.65mg; Datasheet: Y:\MIS_DATABASE\DATASHEETS\RESISTORS\CRCW0603.PDF
R111 = RESISTOR: RES 0.015E 1W 1% AUTO 1206 (HP); Chkd/date: MANIRAJA/210421; Crtd /date: ALVY/210421; Custom_Duty: 15%; Customs_HS_Code: 85332119; Distributor_name: DIGIKEY; Distributor_part_number: WSLP-.015CT-ND; Footprint Path: Y:\MIS_DATABASE\Library\ALTIUM_TOOL\PCB_FOOTPRINTS\Altium_Footprint_Lib.PcbLib; Height: 0.89MM; Library Path: Y:\MIS_DATABASE\Library\ALTIUM_TOOL\SCHEMATICS_PARTS\MS_DISCRETE_Library.schlib; Mfr_name: VISHAY; Mfr_part_number: WSLP1206R0150FEA; Mistral Part No: 110021040031-R; Package: 1206; Part_type: RESISTORS\FIXED; Project: SP_EP2_RX BRD; RoHS: RoHS; Temperature: -65°C+170°C; Tolerance: 1%; Voltage: NA; Wattage: 1W; Weight: 16.2mg; Datasheet: Y:\MIS_DATABASE\DATASHEETS\RESISTORS\WSLP-SERIES.PDF
R112 R119 = RESISTOR: RES 49.9E 1/16W 1% 0402; Chkd/date: MANIRAJA/210519; Crtd /date: MANIRAJA/210519; Custom_Duty: 15%; Customs_HS_Code: 85332119; Distributor_name: DIGIKEY; Distributor_part_number: 541-3967-1-ND; Footprint Path: Y:\MIS_DATABASE\Library\ALTIUM_TOOL\PCB_FOOTPRINTS\Altium_Footprint_Lib.PcbLib; Height: 0.35MM; Library Path: Y:\MIS_DATABASE\Library\ALTIUM_TOOL\SCHEMATICS_PARTS\MS_DISCRETE_Library.schlib; Mfr_name: VISHAY; Mfr_part_number: CRCW040249R9FKEDC; Mistral Part No: 110009030846-R; Package: 0402; Part_type: RESISTORS\FIXED; Project: RFSU_RFTJ_CARD; RoHS: RoHS; Temperature: -55°C+155°C; Tolerance: 1%; Voltage: NA; Wattage: 1/16W; Weight: 0.65mg; Datasheet: Y:\MIS_DATABASE\DATASHEETS\RESISTORS\CRCW_C-SER.PDF
R116 = RESISTOR: RES 0.006E 1W 1% 1206; Chkd/date: MANIRAJA/130519; Crtd /date: ALVY/100519; Custom_Duty: 15%; Customs_HS_Code: 85332119; Distributor_name: DIGIKEY; Distributor_part_number: RHM.006ALCT-ND; Footprint Path: Y:\MIS_DATABASE\Library\ALTIUM_TOOL\PCB_FOOTPRINTS\Altium_Footprint_Lib.PcbLib; Height: 0.59MM; Library Path: Y:\MIS_DATABASE\Library\ALTIUM_TOOL\SCHEMATICS_PARTS\MS_DISCRETE_Library.schlib; Mfr_name: ROHM; Mfr_part_number: PMR18EZPFU6L00; Mistral Part No: 110019050013-R; Package: 1206; Part_type: RESISTORS\FIXED; Project: BRUKER_SD820_COMMONDO; RoHS: RoHS; Temperature: -55°C+155°C; Tolerance: 1%; Voltage: NA; Wattage: 1W; Weight: 16.2mg; Datasheet: Y:\MIS_DATABASE\DATASHEETS\RESISTORS\PMR-SER_REVG.PDF
R129 R130 R317-R319 R321 = RESISTOR: RES 10.2E 1/16W 1% 0402; Chkd/date: MANIRAJA/030817; Crtd /date: MANIRAJA/030817; Custom_Duty: 15%; Customs_HS_Code: 85332119; Distributor_name: DIGIKEY; Distributor_part_number: 541-10.2LCT-ND; Footprint Path: Y:\MIS_DATABASE\Library\ALTIUM_TOOL\PCB_FOOTPRINTS\Altium_Footprint_Lib.PcbLib; Height: 0.40MM; Library Path: Y:\MIS_DATABASE\Library\ALTIUM_TOOL\SCHEMATICS_PARTS\MS_DISCRETE_Library.schlib; Mfr_name: VISHAY; Mfr_part_number: CRCW040210R2FKED; Mistral Part No: 110017080001-R; Package: 0402; Part_type: RESISTORS\FIXED; Project: TI_SVB_DUT; RoHS: RoHS; Temperature: -55°C+155°C; Tolerance: 1%; Voltage: NA; Wattage: 1/16W; Weight: 0.65mg; Datasheet: Y:\MIS_DATABASE\DATASHEETS\RESISTORS\CRCW0603.PDF
R131 R294 = RESISTOR: RES 10K 1/16W 1% 0402; Chkd/date: VASANTHA/201216; Crtd /date: GEETHA/290506; Custom_Duty: 15%; Customs_HS_Code: 85332119; Distributor_name: DIGIKEY; Distributor_part_number: 311-10.0KLRTR-ND; Footprint Path: Y:\MIS_DATABASE\Library\ALTIUM_TOOL\PCB_FOOTPRINTS\Altium_Footprint_Lib.PcbLib; Height: 0.40MM; Library Path: Y:\MIS_DATABASE\Library\ALTIUM_TOOL\SCHEMATICS_PARTS\MS_DISCRETE_Library.schlib; Mfr_name: YAGEO AMERICA; Mfr_part_number: RC0402FR-0710KL; Mistral Part No: 110015090015-R; Package: 0402; Part_type: RESISTORS\FIXED; Project: VOCERA; RoHS: RoHS; Temperature: -55°C+155°C; Tolerance: 1%; Voltage: NA; Wattage: 1/16W; Weight: 0.65mg; Datasheet: Y:\MIS_DATABASE\DATASHEETS\RESISTORS\RCXXXXL-SER_MAR18.PDF
R134 R408 = RESISTOR: RES 100K 1/16W 5% 0402; Chkd/date: VASANTHA/061216; Crtd /date: BAVISH/010611; Custom_Duty: 15%; Customs_HS_Code: 85332119; Distributor_name: DIGIKEY; Distributor_part_number: 541-100KJCT-ND; Footprint Path: Y:\MIS_DATABASE\Library\ALTIUM_TOOL\PCB_FOOTPRINTS\Altium_Footprint_Lib.PcbLib; Height: 0.40MM; Library Path: Y:\MIS_DATABASE\Library\ALTIUM_TOOL\SCHEMATICS_PARTS\MS_DISCRETE_Library.schlib; Mfr_name: VISHAY; Mfr_part_number: CRCW0402100KJNED; Mistral Part No: 110011060002-R; Package: 0402; Part_type: RESISTORS\FIXED; Project: AM4515_EVM_LCD; RoHS: RoHS; Temperature: -55°C+155°C; Tolerance: 5%; Voltage: NA; Wattage: 1/16W; Weight: 0.65mg; Datasheet: Y:\MIS_DATABASE\DATASHEETS\RESISTORS\CRCW0603.PDF
R141 = RESISTOR: RES 3.92K 1/16W 1% 0402; Chkd/date: MANIRAJA/020118; Crtd /date: ALVY/020118; Custom_Duty: 15%; Customs_HS_Code: 85332119; Distributor_name: DIGIKEY; Distributor_part_number: 541-3.92KLCT-ND; Footprint Path: Y:\MIS_DATABASE\Library\ALTIUM_TOOL\PCB_FOOTPRINTS\Altium_Footprint_Lib.PcbLib; Height: 0.40MM; Library Path: Y:\MIS_DATABASE\Library\ALTIUM_TOOL\SCHEMATICS_PARTS\MS_DISCRETE_Library.schlib; Mfr_name: VISHAY; Mfr_part_number: CRCW04023K92FKED; Mistral Part No: 110018010004-R; Package: 0402; Part_type: RESISTORS\FIXED; Project: MS_DRDL_ITS2-SC; RoHS: RoHS; Temperature: -55°C+155°C; Tolerance: 1%; Voltage: NA; Wattage: 1/16W; Weight: 0.65mg; Datasheet: Y:\MIS_DATABASE\DATASHEETS\RESISTORS\CRCW0603.PDF
R142 = RESISTOR: RES 2.2K 1/16W 5% 0402; Chkd/date: VASANTHA/061216; Crtd /date: BAVISH/021210; Custom_Duty: 15%; Customs_HS_Code: 85332119; Distributor_name: DIGIKEY; Distributor_part_number: 311-2.2KJRCT-ND; Footprint Path: Y:\MIS_DATABASE\Library\ALTIUM_TOOL\PCB_FOOTPRINTS\Altium_Footprint_Lib.PcbLib; Height: 0.40MM; Library Path: Y:\MIS_DATABASE\Library\ALTIUM_TOOL\SCHEMATICS_PARTS\MS_DISCRETE_Library.schlib; Mfr_name: YAGEO AMERICA; Mfr_part_number: RC0402JR-072K2L; Mistral Part No: 110010120018-R; Package: 0402; Part_type: RESISTORS\FIXED; Project: TE4; RoHS: RoHS; Temperature: -55°C+155°C; Tolerance: 5%; Voltage: NA; Wattage: 1/16W; Weight: 0.65mg; Datasheet: Y:\MIS_DATABASE\DATASHEETS\RESISTORS\RCXXXXL-SER_MAR18.PDF
R276 R362 R407 = RESISTOR: RES 220E 1/10W 5% 0402; Chkd/date: VASANTHA/291216; Crtd /date: GEETHA/260406; Custom_Duty: 15%; Customs_HS_Code: 85332119; Distributor_name: DIGIKEY; Distributor_part_number: P220JCT-ND; Footprint Path: Y:\MIS_DATABASE\Library\ALTIUM_TOOL\PCB_FOOTPRINTS\Altium_Footprint_Lib.PcbLib; Height: 0.40MM; Library Path: Y:\MIS_DATABASE\Library\ALTIUM_TOOL\SCHEMATICS_PARTS\MS_DISCRETE_Library.schlib; Mfr_name: PANASONIC-ECG; Mfr_part_number: ERJ-2GEJ221X; Mistral Part No: 110009030506-R; Package: 0402; Part_type: RESISTORS\FIXED; Project: RED EYE; RoHS: RoHS; Temperature: -55°C+155°C; Tolerance: 5%; Voltage: NA; Wattage: 1/10W; Weight: 0.8mg; Datasheet: Y:\MIS_DATABASE\DATASHEETS\RESISTORS\PAN-ERJSER_NOV17.PDF
R277 = RESISTOR: RES 51.1E 1/16W 1% 0402; Chkd/date: MANIRAJA/280617; Crtd /date: MANIRAJA/280617; Custom_Duty: 15%; Customs_HS_Code: 85332119; Distributor_name: DIGIKEY; Distributor_part_number: 311-51.1LRCT-ND; Footprint Path: Y:\MIS_DATABASE\Library\ALTIUM_TOOL\PCB_FOOTPRINTS\Altium_Footprint_Lib.PcbLib; Height: 0.40MM; Library Path: Y:\MIS_DATABASE\Library\ALTIUM_TOOL\SCHEMATICS_PARTS\MS_DISCRETE_Library.schlib; Mfr_name: YAGEO AMERICA; Mfr_part_number: RC0402FR-0751R1L; Mistral Part No: 110017060001-R; Package: 0402; Part_type: RESISTORS\FIXED; Project: TI_SVB_CONTROLLER CARD; RoHS: RoHS; Temperature: -55°C+155°C; Tolerance: 1%; Voltage: NA; Wattage: 1/16W; Weight: 0.65mg; Datasheet: Y:\MIS_DATABASE\DATASHEETS\RESISTORS\RCXXXXL-SER_MAR18.PDF
R279 = RESISTOR: RES 31.6K 1/10W 1% 0402; Chkd/date: SHREESHAIL/070606; Crtd /date: SHREESHAIL/070606; Custom_Duty: 15%; Customs_HS_Code: 85332119; Distributor_name: DIGIKEY; Distributor_part_number: P31.6KLCT-ND; Footprint Path: Y:\MIS_DATABASE\Library\ALTIUM_TOOL\PCB_FOOTPRINTS\Altium_Footprint_Lib.PcbLib; Height: 0.40MM; Library Path: Y:\MIS_DATABASE\Library\ALTIUM_TOOL\SCHEMATICS_PARTS\MS_DISCRETE_Library.schlib; Mfr_name: PANASONIC-ECG; Mfr_part_number: ERJ-2RKF3162X; Mistral Part No: 110009030679-R; Package: 0402; Part_type: RESISTORS\FIXED; Project: VOCERA; RoHS: RoHS; Temperature: -55°C+155°C; Tolerance: 1%; Voltage: NA; Wattage: 1/10W; Weight: 0.8mg; Datasheet: Y:\MIS_DATABASE\DATASHEETS\RESISTORS\PAN-ERJSER_NOV17.PDF
R602 = RESISTOR: RES 10K 1/16W 5% 0402; Chkd/date: VASANTHA/061216; Crtd /date: MAZHAR/230805; Custom_Duty: 15%; Customs_HS_Code: 85332119; Distributor_name: DIGIKEY; Distributor_part_number: 311-10KJRCT-ND; Footprint Path: Y:\MIS_DATABASE\Library\ALTIUM_TOOL\PCB_FOOTPRINTS\Altium_Footprint_Lib.PcbLib; Height: 0.40MM; Library Path: Y:\MIS_DATABASE\Library\ALTIUM_TOOL\SCHEMATICS_PARTS\MS_DISCRETE_Library.schlib; Mfr_name: YAGEO AMERICA; Mfr_part_number: RC0402JR-0710KL; Mistral Part No: 110011060021-R; Package: 0402; Part_type: RESISTORS\FIXED; Project: HSE; RoHS: RoHS; Temperature: -55°C+155°C; Tolerance: 5%; Voltage: NA; Wattage: 1/16W; Weight: 0.65mg; Datasheet: Y:\MIS_DATABASE\DATASHEETS\RESISTORS\RCXXXXL-SER_MAR18.PDF
R695 = RESISTOR: RES 2.2E 1/5W 5% 0603; Chkd/date: MANIRAJA/260421; Crtd /date: ALVY/260421; Custom_Duty: 15%; Customs_HS_Code: 85332119; Distributor_name: DIGIKEY; Distributor_part_number: P16036CT-ND; Footprint Path: Y:\MIS_DATABASE\Library\ALTIUM_TOOL\PCB_FOOTPRINTS\Altium_Footprint_Lib.PcbLib; Height: 0.55MM; Library Path: Y:\MIS_DATABASE\Library\ALTIUM_TOOL\SCHEMATICS_PARTS\MS_DISCRETE_Library.schlib; Mfr_name: PANASONIC-ECG; Mfr_part_number: ERJ-P03J2R2V; Mistral Part No: 110021040040-R; Package: 0603; Part_type: RESISTORS\FIXED; Project: SP_EP2_RX BRD; RoHS: RoHS; Temperature: -55°C+155°C; Tolerance: 5%; Voltage: NA; Wattage: 1/5W; Weight: 2mg; Datasheet: Y:\MIS_DATABASE\DATASHEETS\RESISTORS\ERJ-PA_P0-SER.PDF
SW1 = SW3_B12JV: SWITCH TOGGLE SPDT RT TH; Chkd/date: MANIRAJA/291217; Crtd /date: MANIRAJA/291217; Custom_Duty: 24%; Customs_HS_Code: 85369090; Distributor_name: DIGIKEY; Distributor_part_number: 563-1759-ND; Height: 5.60MM; Mfr_name: NIDEC COPAL; Mistral Part No: 130017120017-R; Package: THRU-HOLE; Part_type: ELECTRO-MECHANICAL\SWITCH; Project: TI_MAXIE_CPB; RoHS: RoHS; Temperature: -20°C+85°C; Tolerance: NA; Voltage: NA; Wattage: NA; Weight: NA; Datasheet: Y:\MIS_DATABASE\DATASHEETS\MISC\SWITCHES\ATE-SER.PDF
TP12 TP18 TP44 = TESTPOINT: TESTPOINT 1.0MM DRILL PTH; Chkd/date: MAZHAR/271211; Crtd /date: SHREESHAIL/041005; Distributor_name: NA; Distributor_part_number: NA; Height: NA; Mfr_name: LOCAL; Mistral Part No: 130009030938; Package: THRU-HOLE; Project: HSE; Datasheet: NA
U17 = TPS54334DRCT_VSON10: IC 3A O/P CURRENT SYNCHRONOUS STEP DOWN VOLTAGE CONVERTER VSON10; Chkd/date: MANIRAJA/270917; Crtd /date: MANIRAJA/270917; Custom_Duty: 15%; Customs_HS_Code: 85423100; Distributor_name: DIGIKEY; Distributor_part_number: 296-42172-2-ND; Height: 1.00MM; Mfr_name: TEXAS INSTRUMENTS; Mistral Part No: 142017090024-R; Package: VSON10; Part_type: ICS\POWER\CONVERTER; Project: TI_MAXIE_CPB; RoHS: RoHS; Temperature: -40°C+85°C; Tolerance: NA; Voltage: NA; Wattage: NA; Weight: 30mg; Datasheet: Y:\MIS_DATABASE\DATASHEETS\ICS\POWER\TPS54334.PDF
U21 U22 U24 U26 = MOSFET_CSD18501Q5A: IC MOSFET N-CHANNEL 60V VSONP8; Chkd/date: MANIRAJA/041017; Crtd /date: MANIRAJA/041017; Custom_Duty: 15%; Customs_HS_Code: 85423100; Distributor_name: DIGIKEY; Distributor_part_number: 296-47321-1-ND; Footprint Path: Y:\MIS_DATABASE\Library\ALTIUM_TOOL\PCB_FOOTPRINTS\Altium_Footprint_Lib.PcbLib; Height: 0.90MM; Library Path: Y:\MIS_DATABASE\Library\ALTIUM_TOOL\SCHEMATICS_PARTS\MS_MOSFET_Library.schlib; Mfr_name: TEXAS INSTRUMENTS; Mistral Part No: 142017100004-R; Package: VSONP8; Part_type: ICS\POWER\MOSFET; Project: TI_MAXIE_CPB; RoHS: RoHS; Temperature: -55°C+150°C; Tolerance: NA; Voltage: 60V; Wattage: NA; Weight: NA; Datasheet: Y:\MIS_DATABASE\DATASHEETS\ICS\POWER\CSD18543Q3A.PDF
U30 = LM5140QRWGTQ1_VQFNP40: IC WIDE I/P DUAL SYNCHRONOUS BUCK CONTROLLER VQFNP40; Chkd/date: MANIRAJA/041017; Crtd /date: MANIRAJA/041017; Custom_Duty: 15%; Customs_HS_Code: 85423100; Distributor_name: DIGIKEY; Distributor_part_number: 296-43790-1-ND; Footprint Path: Y:\MIS_DATABASE\Library\ALTIUM_TOOL\PCB_FOOTPRINTS\Altium_Footprint_Lib.PcbLib; Height: 0.90MM; Library Path: Y:\MIS_DATABASE\Library\ALTIUM_TOOL\SCHEMATICS_PARTS\MS_MISCPOWER_Library.schlib; Mfr_name: TEXAS INSTRUMENTS; Mistral Part No: 142017100003-R; Package: VQFNP40; Part_type: ICS\POWER\CONVERTER; Project: TI_MAXIE_CPB; RoHS: RoHS; Temperature: -40°C+150°C; Tolerance: NA; Voltage: NA; Wattage: NA; Weight: 104mg; Datasheet: Y:\MIS_DATABASE\DATASHEETS\ICS\POWER\LM5140QRWGXX.PDF
U102 = SN74LVC1G32DBVR_SOT23-5: IC SINGAL 2 INPUT POSITIVE OR GATE SOT23-5; Chkd/date: MANIRAJA/051017; Crtd /date: MAZHAR/070806; Custom_Duty: 15%; Customs_HS_Code: 85423100; Distributor_name: DIGIKEY; Distributor_part_number: 296-9847-1-ND; Height: 1.45MM; Mfr_name: TEXAS INSTRUMENTS; Mistral Part No: 141009030236-R; Package: SOT23-5; Part_type: ICS\DIGITAL\GATES; Project: SVDO_RMB_MMA; RoHS: RoHS; Temperature: -40°C+85°C; Tolerance: NA; Voltage: NA; Wattage: NA; Weight: 6.3mg; Datasheet: Y:\MIS_DATABASE\DATASHEETS\ICS\DIGITAL\GATES\SN74LVC1G32.PDF

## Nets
DGND: C40.2 C46.2 C48.1 C49.2 C65.1 C66.2 C69.2 C70.2 C71.2 C81.2 C82.2 C84.2 C107.2 C108.2 C118.2 C123.2 C125.2 C130.2 C131.2 C132.2 C135.1 C136.2 C137.1 C138.2 C406.2 C494.1 C539.2 LD4.1(CATHODE) LD9.1(CATHODE) LD15.1(CATHODE) R294.2 R602.1 R694.2 SW1.1 SW1.SH1 SW1.SH2 U17.3(GND) U17.4(GND) U17.5(GND) U17.11(EP) U21.1(S1) U21.2(S2) U21.3(S3) U22.1(S1) U22.2(S2) U22.3(S3) U30.14(PGND2) U30.17(PGND1) U30.35(AGND) U30.38(SYNIN) U30.41(EP) U102.3(GND) ; also on sheet 2 3 4 5 6 7 8 9 10 11 12 13 14 15 16 18 19 20 21 22 23 24 25 26 27 28 29 30 39 40
VCC3V3_PREREG: C40.1 C46.1 L3.2 R276.1 R277.1 TP12.1(TP) ; also on sheet 15 25
VCC3V3_PREREG_EN: R579.2 U102.4(Y)
VCC3V3_SYS_PG: C118.1 R131.2 U30.24(PG1) ; also on sheet 15 16
VCC3V3_TA: C494.2 U102.5(VCC) ; also on sheet 16 29 30
VCC5V0_PG: R134.1 U30.7(PG2) U102.1(A)
VCC_3V3_SYS: C70.1 C84.1 R113.1 R116.1 R131.1 R362.1 TP44.1(TP) ; also on sheet 2 5 6 7 8 10 11 12 13 14 15 16 18 19 20 21 23 24 25 26 27 29 30 39 40
VCC_5V0: C69.1 C71.1 C539.1 R109.1 R111.2 R407.1 TP18.1(TP) U30.6(VCCX) ; also on sheet 4 6 18 20 25
VCC_CORE_PG: U102.2(B) ; also on sheet 8 15
VCC_LM5140: C107.1 C108.1 D4.2(ANODE) D5.2(ANODE) U30.15(VCC) U30.16(VCC)
VDDA_LM5140: C138.1 R134.2 R693.1 U30.3(FB2) U30.28(FB1) U30.34(ILSET) U30.36(VDDA) U30.37(OSC)
VIN_MON_PORz_3V3_PG: R578.2 U17.10(PGOOD) ; also on sheet 16 25
DEMB: R693.2 R694.1 U30.33(DEMB)
LM5140_COMP1: C135.2 R142.1 U30.29(COMP1)
LM5140_COMP2: C130.1 R141.2 U30.2(COMP2)
TEST_POWERDOWN: R412.1 ; also on sheet 30
VMAIN: C65.2 C66.1 C81.1 C82.1 C123.1 R408.2 R695.1 U17.1(VIN) U24.5(D) U26.5(D) ; also on sheet 4 5 8 16
VMAIN_EN: C406.1 R408.1 R412.2 R577.1 SW1.2
VSENSE: C272.2 R279.2 R294.1 U17.6(VSENSE)
N19753713: C116.2 D5.1(CATHODE) U30.11(HB2)
N19753729: C116.1 L5.1 U22.5(D) U26.1(S1) U26.2(S2) U26.3(S3) U30.10(SW2)
N19753760: L5.2 R111.1 R112.1
N19753772: R129.2 U26.4(G) U30.8(HOL2)
N19753820: R317.1 U30.13(LO2)
N19753822: R317.2 R321.2 U22.4(G)
N19753872: C85.1 R112.2 U30.4(CS2)
N19753878: C85.2 R109.2 U30.5(VOUT2)
N19753964: C125.1 R141.1
N19754006: C131.1 U30.30(SS1)
N19754159: R695.2 U30.25(VIN)
N19754185: C132.1 U30.1(SS2)
N19754201: C115.2 L6.2 U21.5(D) U24.1(S1) U24.2(S2) U24.3(S3) U30.21(SW1)
N19754203: C115.1 D4.1(CATHODE) U30.20(HB1)
N19754223: R130.2 U30.22(HO1)
N19754237: R130.1 U24.4(G) U30.23(HOL1)
N19754314: R318.1 R319.1 U21.4(G)
N19754320: R319.2 U30.19(LOL1)
N19754322: R318.2 U30.18(LO1)
N19754431: R129.1 U30.9(HO2)
N19754435: R321.1 U30.12(LOL2)
N19754522: L6.1 R116.2 R119.1
N19754526: C94.1 R113.2 U30.26(VOUT1)
N19754534: C94.2 R119.2 U30.27(CS1)
N19754630: C137.2 U30.32(RES)
N19754677: C136.1 R142.2
N26004018: C49.1 R82.1 U17.7(COMP)
N26004022: C48.2 R82.2
N26004036: C54.1 L3.1 U17.2(SW)
N26004038: C54.2 U17.9(BOOT)
N26004052: C272.1 R277.2 R279.1
N27914276: R577.2 U30.40(EN2)
N27928121: R578.1 U30.31(EN1)
N27928168: R579.1 R602.2 U17.8(EN)
N28118260: LD4.2(ANODE) R276.2
N28118377: LD9.2(ANODE) R362.2
N28118380: LD15.2(ANODE) R407.2

Not connected (* = marked no-connect by the designer): SW1 3*; U30 39(SYNOUT)*

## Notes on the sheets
sheet 17
- VCC3V3_SYS & VCC_5V0 POWER SUPPLY
- 5V,3A and 3.3V,7A Dual SUPPLY
- NOTE :
  Iout for 3.3V is Considered as 7A Max
- NOTE :
  Iout for 5V is Considered as 3A Max
- Off Page Connections
- ON/ OFF Control SWITCH
- PREREG 3.3V, 3.0AMPS SUPPLY
